VERSION 5.7 ;
  NOWIREEXTENSIONATPIN ON ;
  DIVIDERCHAR "/" ;
  BUSBITCHARS "[]" ;
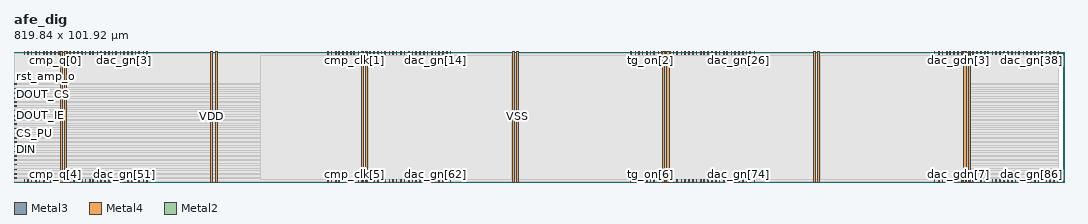
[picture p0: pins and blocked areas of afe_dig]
MACRO afe_dig
  CLASS BLOCK ;
  FOREIGN afe_dig ;
  ORIGIN 0.000 0.000 ;
  SIZE 819.840 BY 101.920 ;
  PIN CS
    DIRECTION INPUT ;
    USE SIGNAL ;
    ANTENNAGATEAREA 25.052999 ;
    PORT
      LAYER Metal3 ;
        RECT 0.000 41.440 2.000 42.000 ;
    END
  END CS
  PIN CS_PD
    DIRECTION OUTPUT ;
    USE SIGNAL ;
    ANTENNADIFFAREA 0.360800 ;
    PORT
      LAYER Metal3 ;
        RECT 0.000 34.160 2.000 34.720 ;
    END
  END CS_PD
  PIN CS_PU
    DIRECTION OUTPUT ;
    USE SIGNAL ;
    ANTENNADIFFAREA 0.360800 ;
    PORT
      LAYER Metal3 ;
        RECT 0.000 37.520 2.000 38.080 ;
    END
  END CS_PU
  PIN DIN
    DIRECTION INPUT ;
    USE SIGNAL ;
    ANTENNAGATEAREA 1.102000 ;
    PORT
      LAYER Metal3 ;
        RECT 0.000 30.800 2.000 31.360 ;
    END
  END DIN
  PIN DIN_PD
    DIRECTION OUTPUT ;
    USE SIGNAL ;
    ANTENNADIFFAREA 0.360800 ;
    PORT
      LAYER Metal3 ;
        RECT 0.000 23.520 2.000 24.080 ;
    END
  END DIN_PD
  PIN DIN_PU
    DIRECTION OUTPUT ;
    USE SIGNAL ;
    ANTENNADIFFAREA 0.360800 ;
    PORT
      LAYER Metal3 ;
        RECT 0.000 27.440 2.000 28.000 ;
    END
  END DIN_PU
  PIN DOUT
    DIRECTION OUTPUT ;
    USE SIGNAL ;
    ANTENNADIFFAREA 2.080000 ;
    PORT
      LAYER Metal3 ;
        RECT 0.000 44.800 2.000 45.360 ;
    END
  END DOUT
  PIN DOUT_CS
    DIRECTION OUTPUT ;
    USE SIGNAL ;
    ANTENNADIFFAREA 0.360800 ;
    PORT
      LAYER Metal3 ;
        RECT 0.000 62.160 2.000 62.720 ;
    END
  END DOUT_CS
  PIN DOUT_IE
    DIRECTION OUTPUT ;
    USE SIGNAL ;
    ANTENNADIFFAREA 0.360800 ;
    PORT
      LAYER Metal3 ;
        RECT 0.000 51.520 2.000 52.080 ;
    END
  END DOUT_IE
  PIN DOUT_OE
    DIRECTION OUTPUT ;
    USE SIGNAL ;
    ANTENNADIFFAREA 10.059999 ;
    PORT
      LAYER Metal3 ;
        RECT 0.000 48.160 2.000 48.720 ;
    END
  END DOUT_OE
  PIN DOUT_PD
    DIRECTION OUTPUT ;
    USE SIGNAL ;
    ANTENNADIFFAREA 0.360800 ;
    PORT
      LAYER Metal3 ;
        RECT 0.000 55.440 2.000 56.000 ;
    END
  END DOUT_PD
  PIN DOUT_PDRV0
    DIRECTION OUTPUT ;
    USE SIGNAL ;
    ANTENNADIFFAREA 0.360800 ;
    PORT
      LAYER Metal3 ;
        RECT 0.000 69.440 2.000 70.000 ;
    END
  END DOUT_PDRV0
  PIN DOUT_PDRV1
    DIRECTION OUTPUT ;
    USE SIGNAL ;
    ANTENNADIFFAREA 0.360800 ;
    PORT
      LAYER Metal3 ;
        RECT 0.000 72.800 2.000 73.360 ;
    END
  END DOUT_PDRV1
  PIN DOUT_PU
    DIRECTION OUTPUT ;
    USE SIGNAL ;
    ANTENNADIFFAREA 0.360800 ;
    PORT
      LAYER Metal3 ;
        RECT 0.000 58.800 2.000 59.360 ;
    END
  END DOUT_PU
  PIN DOUT_SL
    DIRECTION OUTPUT ;
    USE SIGNAL ;
    ANTENNADIFFAREA 0.360800 ;
    PORT
      LAYER Metal3 ;
        RECT 0.000 65.520 2.000 66.080 ;
    END
  END DOUT_SL
  PIN RSTN
    DIRECTION INPUT ;
    USE SIGNAL ;
    ANTENNAGATEAREA 177.865494 ;
    PORT
      LAYER Metal3 ;
        RECT 0.000 9.520 2.000 10.080 ;
    END
  END RSTN
  PIN RSTN_PD
    DIRECTION OUTPUT ;
    USE SIGNAL ;
    ANTENNADIFFAREA 0.536800 ;
    PORT
      LAYER Metal3 ;
        RECT 0.000 2.800 2.000 3.360 ;
    END
  END RSTN_PD
  PIN RSTN_PU
    DIRECTION OUTPUT ;
    USE SIGNAL ;
    ANTENNADIFFAREA 0.360800 ;
    PORT
      LAYER Metal3 ;
        RECT 0.000 6.160 2.000 6.720 ;
    END
  END RSTN_PU
  PIN SCLK
    DIRECTION INPUT ;
    USE SIGNAL ;
    ANTENNAGATEAREA 5.924000 ;
    PORT
      LAYER Metal3 ;
        RECT 0.000 20.160 2.000 20.720 ;
    END
  END SCLK
  PIN SCLK_PD
    DIRECTION OUTPUT ;
    USE SIGNAL ;
    ANTENNADIFFAREA 0.360800 ;
    PORT
      LAYER Metal3 ;
        RECT 0.000 13.440 2.000 14.000 ;
    END
  END SCLK_PD
  PIN SCLK_PU
    DIRECTION OUTPUT ;
    USE SIGNAL ;
    ANTENNADIFFAREA 0.360800 ;
    PORT
      LAYER Metal3 ;
        RECT 0.000 16.800 2.000 17.360 ;
    END
  END SCLK_PU
  PIN VDD
    DIRECTION INOUT ;
    USE POWER ;
    PORT
      LAYER Metal4 ;
        RECT 36.160 0.000 37.760 101.920 ;
    END
    PORT
      LAYER Metal4 ;
        RECT 153.760 0.000 155.360 101.920 ;
    END
    PORT
      LAYER Metal4 ;
        RECT 271.360 0.000 272.960 101.920 ;
    END
    PORT
      LAYER Metal4 ;
        RECT 388.960 0.000 390.560 101.920 ;
    END
    PORT
      LAYER Metal4 ;
        RECT 506.560 0.000 508.160 101.920 ;
    END
    PORT
      LAYER Metal4 ;
        RECT 624.160 0.000 625.760 101.920 ;
    END
    PORT
      LAYER Metal4 ;
        RECT 741.760 0.000 743.360 101.920 ;
    END
  END VDD
  PIN VSS
    DIRECTION INOUT ;
    USE GROUND ;
    PORT
      LAYER Metal4 ;
        RECT 39.460 0.000 41.060 101.920 ;
    END
    PORT
      LAYER Metal4 ;
        RECT 157.060 0.000 158.660 101.920 ;
    END
    PORT
      LAYER Metal4 ;
        RECT 274.660 0.000 276.260 101.920 ;
    END
    PORT
      LAYER Metal4 ;
        RECT 392.260 0.000 393.860 101.920 ;
    END
    PORT
      LAYER Metal4 ;
        RECT 509.860 0.000 511.460 101.920 ;
    END
    PORT
      LAYER Metal4 ;
        RECT 627.460 0.000 629.060 101.920 ;
    END
    PORT
      LAYER Metal4 ;
        RECT 745.060 0.000 746.660 101.920 ;
    END
  END VSS
  PIN cmp_clk[0]
    DIRECTION OUTPUT ;
    USE SIGNAL ;
    ANTENNADIFFAREA 0.875600 ;
    PORT
      LAYER Metal2 ;
        RECT 28.560 99.920 29.120 101.920 ;
    END
  END cmp_clk[0]
  PIN cmp_clk[1]
    DIRECTION OUTPUT ;
    USE SIGNAL ;
    ANTENNADIFFAREA 0.875600 ;
    PORT
      LAYER Metal2 ;
        RECT 265.440 99.920 266.000 101.920 ;
    END
  END cmp_clk[1]
  PIN cmp_clk[2]
    DIRECTION OUTPUT ;
    USE SIGNAL ;
    ANTENNADIFFAREA 0.875600 ;
    PORT
      LAYER Metal2 ;
        RECT 502.880 99.920 503.440 101.920 ;
    END
  END cmp_clk[2]
  PIN cmp_clk[3]
    DIRECTION OUTPUT ;
    USE SIGNAL ;
    ANTENNADIFFAREA 0.875600 ;
    PORT
      LAYER Metal2 ;
        RECT 739.760 99.920 740.320 101.920 ;
    END
  END cmp_clk[3]
  PIN cmp_clk[4]
    DIRECTION OUTPUT ;
    USE SIGNAL ;
    ANTENNADIFFAREA 0.875600 ;
    PORT
      LAYER Metal2 ;
        RECT 28.560 0.000 29.120 2.000 ;
    END
  END cmp_clk[4]
  PIN cmp_clk[5]
    DIRECTION OUTPUT ;
    USE SIGNAL ;
    ANTENNADIFFAREA 0.875600 ;
    PORT
      LAYER Metal2 ;
        RECT 265.440 0.000 266.000 2.000 ;
    END
  END cmp_clk[5]
  PIN cmp_clk[6]
    DIRECTION OUTPUT ;
    USE SIGNAL ;
    ANTENNADIFFAREA 0.875600 ;
    PORT
      LAYER Metal2 ;
        RECT 502.880 0.000 503.440 2.000 ;
    END
  END cmp_clk[6]
  PIN cmp_clk[7]
    DIRECTION OUTPUT ;
    USE SIGNAL ;
    ANTENNADIFFAREA 0.875600 ;
    PORT
      LAYER Metal2 ;
        RECT 739.760 0.000 740.320 2.000 ;
    END
  END cmp_clk[7]
  PIN cmp_q[0]
    DIRECTION INPUT ;
    USE SIGNAL ;
    ANTENNAGATEAREA 0.396000 ;
    PORT
      LAYER Metal2 ;
        RECT 31.920 99.920 32.480 101.920 ;
    END
  END cmp_q[0]
  PIN cmp_q[1]
    DIRECTION INPUT ;
    USE SIGNAL ;
    ANTENNAGATEAREA 0.396000 ;
    PORT
      LAYER Metal2 ;
        RECT 268.800 99.920 269.360 101.920 ;
    END
  END cmp_q[1]
  PIN cmp_q[2]
    DIRECTION INPUT ;
    USE SIGNAL ;
    ANTENNAGATEAREA 0.396000 ;
    PORT
      LAYER Metal2 ;
        RECT 505.680 99.920 506.240 101.920 ;
    END
  END cmp_q[2]
  PIN cmp_q[3]
    DIRECTION INPUT ;
    USE SIGNAL ;
    ANTENNAGATEAREA 0.396000 ;
    PORT
      LAYER Metal2 ;
        RECT 742.560 99.920 743.120 101.920 ;
    END
  END cmp_q[3]
  PIN cmp_q[4]
    DIRECTION INPUT ;
    USE SIGNAL ;
    ANTENNAGATEAREA 0.396000 ;
    PORT
      LAYER Metal2 ;
        RECT 31.920 0.000 32.480 2.000 ;
    END
  END cmp_q[4]
  PIN cmp_q[5]
    DIRECTION INPUT ;
    USE SIGNAL ;
    ANTENNAGATEAREA 0.396000 ;
    PORT
      LAYER Metal2 ;
        RECT 268.800 0.000 269.360 2.000 ;
    END
  END cmp_q[5]
  PIN cmp_q[6]
    DIRECTION INPUT ;
    USE SIGNAL ;
    ANTENNAGATEAREA 0.396000 ;
    PORT
      LAYER Metal2 ;
        RECT 505.680 0.000 506.240 2.000 ;
    END
  END cmp_q[6]
  PIN cmp_q[7]
    DIRECTION INPUT ;
    USE SIGNAL ;
    ANTENNAGATEAREA 0.396000 ;
    PORT
      LAYER Metal2 ;
        RECT 742.560 0.000 743.120 2.000 ;
    END
  END cmp_q[7]
  PIN dac_gdn[0]
    DIRECTION OUTPUT ;
    USE SIGNAL ;
    ANTENNADIFFAREA 0.748000 ;
    PORT
      LAYER Metal2 ;
        RECT 25.760 99.920 26.320 101.920 ;
    END
  END dac_gdn[0]
  PIN dac_gdn[1]
    DIRECTION OUTPUT ;
    USE SIGNAL ;
    ANTENNADIFFAREA 0.748000 ;
    PORT
      LAYER Metal2 ;
        RECT 262.640 99.920 263.200 101.920 ;
    END
  END dac_gdn[1]
  PIN dac_gdn[2]
    DIRECTION OUTPUT ;
    USE SIGNAL ;
    ANTENNADIFFAREA 0.748000 ;
    PORT
      LAYER Metal2 ;
        RECT 499.520 99.920 500.080 101.920 ;
    END
  END dac_gdn[2]
  PIN dac_gdn[3]
    DIRECTION OUTPUT ;
    USE SIGNAL ;
    ANTENNADIFFAREA 0.748000 ;
    PORT
      LAYER Metal2 ;
        RECT 736.960 99.920 737.520 101.920 ;
    END
  END dac_gdn[3]
  PIN dac_gdn[4]
    DIRECTION OUTPUT ;
    USE SIGNAL ;
    ANTENNADIFFAREA 0.748000 ;
    PORT
      LAYER Metal2 ;
        RECT 25.760 0.000 26.320 2.000 ;
    END
  END dac_gdn[4]
  PIN dac_gdn[5]
    DIRECTION OUTPUT ;
    USE SIGNAL ;
    ANTENNADIFFAREA 0.748000 ;
    PORT
      LAYER Metal2 ;
        RECT 262.640 0.000 263.200 2.000 ;
    END
  END dac_gdn[5]
  PIN dac_gdn[6]
    DIRECTION OUTPUT ;
    USE SIGNAL ;
    ANTENNADIFFAREA 0.748000 ;
    PORT
      LAYER Metal2 ;
        RECT 499.520 0.000 500.080 2.000 ;
    END
  END dac_gdn[6]
  PIN dac_gdn[7]
    DIRECTION OUTPUT ;
    USE SIGNAL ;
    ANTENNADIFFAREA 0.748000 ;
    PORT
      LAYER Metal2 ;
        RECT 736.960 0.000 737.520 2.000 ;
    END
  END dac_gdn[7]
  PIN dac_gn[0]
    DIRECTION OUTPUT ;
    USE SIGNAL ;
    ANTENNADIFFAREA 0.830600 ;
    PORT
      LAYER Metal2 ;
        RECT 103.600 99.920 104.160 101.920 ;
    END
  END dac_gn[0]
  PIN dac_gn[10]
    DIRECTION OUTPUT ;
    USE SIGNAL ;
    ANTENNADIFFAREA 0.830600 ;
    PORT
      LAYER Metal2 ;
        RECT 43.680 99.920 44.240 101.920 ;
    END
  END dac_gn[10]
  PIN dac_gn[11]
    DIRECTION OUTPUT ;
    USE SIGNAL ;
    ANTENNADIFFAREA 0.830600 ;
    PORT
      LAYER Metal2 ;
        RECT 37.520 99.920 38.080 101.920 ;
    END
  END dac_gn[11]
  PIN dac_gn[12]
    DIRECTION OUTPUT ;
    USE SIGNAL ;
    ANTENNADIFFAREA 0.830600 ;
    PORT
      LAYER Metal2 ;
        RECT 340.480 99.920 341.040 101.920 ;
    END
  END dac_gn[12]
  PIN dac_gn[13]
    DIRECTION OUTPUT ;
    USE SIGNAL ;
    ANTENNADIFFAREA 0.830600 ;
    PORT
      LAYER Metal2 ;
        RECT 334.880 99.920 335.440 101.920 ;
    END
  END dac_gn[13]
  PIN dac_gn[14]
    DIRECTION OUTPUT ;
    USE SIGNAL ;
    ANTENNADIFFAREA 0.830600 ;
    PORT
      LAYER Metal2 ;
        RECT 328.720 99.920 329.280 101.920 ;
    END
  END dac_gn[14]
  PIN dac_gn[15]
    DIRECTION OUTPUT ;
    USE SIGNAL ;
    ANTENNADIFFAREA 0.830600 ;
    PORT
      LAYER Metal2 ;
        RECT 322.560 99.920 323.120 101.920 ;
    END
  END dac_gn[15]
  PIN dac_gn[16]
    DIRECTION OUTPUT ;
    USE SIGNAL ;
    ANTENNADIFFAREA 0.830600 ;
    PORT
      LAYER Metal2 ;
        RECT 316.960 99.920 317.520 101.920 ;
    END
  END dac_gn[16]
  PIN dac_gn[17]
    DIRECTION OUTPUT ;
    USE SIGNAL ;
    ANTENNADIFFAREA 0.830600 ;
    PORT
      LAYER Metal2 ;
        RECT 310.800 99.920 311.360 101.920 ;
    END
  END dac_gn[17]
  PIN dac_gn[18]
    DIRECTION OUTPUT ;
    USE SIGNAL ;
    ANTENNADIFFAREA 0.830600 ;
    PORT
      LAYER Metal2 ;
        RECT 304.640 99.920 305.200 101.920 ;
    END
  END dac_gn[18]
  PIN dac_gn[19]
    DIRECTION OUTPUT ;
    USE SIGNAL ;
    ANTENNADIFFAREA 0.830600 ;
    PORT
      LAYER Metal2 ;
        RECT 298.480 99.920 299.040 101.920 ;
    END
  END dac_gn[19]
  PIN dac_gn[1]
    DIRECTION OUTPUT ;
    USE SIGNAL ;
    ANTENNADIFFAREA 0.830600 ;
    PORT
      LAYER Metal2 ;
        RECT 97.440 99.920 98.000 101.920 ;
    END
  END dac_gn[1]
  PIN dac_gn[20]
    DIRECTION OUTPUT ;
    USE SIGNAL ;
    ANTENNADIFFAREA 0.830600 ;
    PORT
      LAYER Metal2 ;
        RECT 292.880 99.920 293.440 101.920 ;
    END
  END dac_gn[20]
  PIN dac_gn[21]
    DIRECTION OUTPUT ;
    USE SIGNAL ;
    ANTENNADIFFAREA 0.830600 ;
    PORT
      LAYER Metal2 ;
        RECT 286.720 99.920 287.280 101.920 ;
    END
  END dac_gn[21]
  PIN dac_gn[22]
    DIRECTION OUTPUT ;
    USE SIGNAL ;
    ANTENNADIFFAREA 0.830600 ;
    PORT
      LAYER Metal2 ;
        RECT 280.560 99.920 281.120 101.920 ;
    END
  END dac_gn[22]
  PIN dac_gn[23]
    DIRECTION OUTPUT ;
    USE SIGNAL ;
    ANTENNADIFFAREA 0.830600 ;
    PORT
      LAYER Metal2 ;
        RECT 274.960 99.920 275.520 101.920 ;
    END
  END dac_gn[23]
  PIN dac_gn[24]
    DIRECTION OUTPUT ;
    USE SIGNAL ;
    ANTENNADIFFAREA 0.830600 ;
    PORT
      LAYER Metal2 ;
        RECT 577.920 99.920 578.480 101.920 ;
    END
  END dac_gn[24]
  PIN dac_gn[25]
    DIRECTION OUTPUT ;
    USE SIGNAL ;
    ANTENNADIFFAREA 0.830600 ;
    PORT
      LAYER Metal2 ;
        RECT 571.760 99.920 572.320 101.920 ;
    END
  END dac_gn[25]
  PIN dac_gn[26]
    DIRECTION OUTPUT ;
    USE SIGNAL ;
    ANTENNADIFFAREA 0.830600 ;
    PORT
      LAYER Metal2 ;
        RECT 565.600 99.920 566.160 101.920 ;
    END
  END dac_gn[26]
  PIN dac_gn[27]
    DIRECTION OUTPUT ;
    USE SIGNAL ;
    ANTENNADIFFAREA 0.830600 ;
    PORT
      LAYER Metal2 ;
        RECT 560.000 99.920 560.560 101.920 ;
    END
  END dac_gn[27]
  PIN dac_gn[28]
    DIRECTION OUTPUT ;
    USE SIGNAL ;
    ANTENNADIFFAREA 0.830600 ;
    PORT
      LAYER Metal2 ;
        RECT 553.840 99.920 554.400 101.920 ;
    END
  END dac_gn[28]
  PIN dac_gn[29]
    DIRECTION OUTPUT ;
    USE SIGNAL ;
    ANTENNADIFFAREA 0.830600 ;
    PORT
      LAYER Metal2 ;
        RECT 547.680 99.920 548.240 101.920 ;
    END
  END dac_gn[29]
  PIN dac_gn[2]
    DIRECTION OUTPUT ;
    USE SIGNAL ;
    ANTENNADIFFAREA 0.830600 ;
    PORT
      LAYER Metal2 ;
        RECT 91.840 99.920 92.400 101.920 ;
    END
  END dac_gn[2]
  PIN dac_gn[30]
    DIRECTION OUTPUT ;
    USE SIGNAL ;
    ANTENNADIFFAREA 0.830600 ;
    PORT
      LAYER Metal2 ;
        RECT 541.520 99.920 542.080 101.920 ;
    END
  END dac_gn[30]
  PIN dac_gn[31]
    DIRECTION OUTPUT ;
    USE SIGNAL ;
    ANTENNADIFFAREA 0.830600 ;
    PORT
      LAYER Metal2 ;
        RECT 535.920 99.920 536.480 101.920 ;
    END
  END dac_gn[31]
  PIN dac_gn[32]
    DIRECTION OUTPUT ;
    USE SIGNAL ;
    ANTENNADIFFAREA 0.830600 ;
    PORT
      LAYER Metal2 ;
        RECT 529.760 99.920 530.320 101.920 ;
    END
  END dac_gn[32]
  PIN dac_gn[33]
    DIRECTION OUTPUT ;
    USE SIGNAL ;
    ANTENNADIFFAREA 0.830600 ;
    PORT
      LAYER Metal2 ;
        RECT 523.600 99.920 524.160 101.920 ;
    END
  END dac_gn[33]
  PIN dac_gn[34]
    DIRECTION OUTPUT ;
    USE SIGNAL ;
    ANTENNADIFFAREA 0.830600 ;
    PORT
      LAYER Metal2 ;
        RECT 517.440 99.920 518.000 101.920 ;
    END
  END dac_gn[34]
  PIN dac_gn[35]
    DIRECTION OUTPUT ;
    USE SIGNAL ;
    ANTENNADIFFAREA 0.830600 ;
    PORT
      LAYER Metal2 ;
        RECT 511.840 99.920 512.400 101.920 ;
    END
  END dac_gn[35]
  PIN dac_gn[36]
    DIRECTION OUTPUT ;
    USE SIGNAL ;
    ANTENNADIFFAREA 0.830600 ;
    PORT
      LAYER Metal2 ;
        RECT 814.800 99.920 815.360 101.920 ;
    END
  END dac_gn[36]
  PIN dac_gn[37]
    DIRECTION OUTPUT ;
    USE SIGNAL ;
    ANTENNADIFFAREA 0.830600 ;
    PORT
      LAYER Metal2 ;
        RECT 808.640 99.920 809.200 101.920 ;
    END
  END dac_gn[37]
  PIN dac_gn[38]
    DIRECTION OUTPUT ;
    USE SIGNAL ;
    ANTENNADIFFAREA 0.830600 ;
    PORT
      LAYER Metal2 ;
        RECT 802.480 99.920 803.040 101.920 ;
    END
  END dac_gn[38]
  PIN dac_gn[39]
    DIRECTION OUTPUT ;
    USE SIGNAL ;
    ANTENNADIFFAREA 0.830600 ;
    PORT
      LAYER Metal2 ;
        RECT 796.880 99.920 797.440 101.920 ;
    END
  END dac_gn[39]
  PIN dac_gn[3]
    DIRECTION OUTPUT ;
    USE SIGNAL ;
    ANTENNADIFFAREA 0.830600 ;
    PORT
      LAYER Metal2 ;
        RECT 85.680 99.920 86.240 101.920 ;
    END
  END dac_gn[3]
  PIN dac_gn[40]
    DIRECTION OUTPUT ;
    USE SIGNAL ;
    ANTENNADIFFAREA 0.830600 ;
    PORT
      LAYER Metal2 ;
        RECT 790.720 99.920 791.280 101.920 ;
    END
  END dac_gn[40]
  PIN dac_gn[41]
    DIRECTION OUTPUT ;
    USE SIGNAL ;
    ANTENNADIFFAREA 0.830600 ;
    PORT
      LAYER Metal2 ;
        RECT 784.560 99.920 785.120 101.920 ;
    END
  END dac_gn[41]
  PIN dac_gn[42]
    DIRECTION OUTPUT ;
    USE SIGNAL ;
    ANTENNADIFFAREA 0.830600 ;
    PORT
      LAYER Metal2 ;
        RECT 778.960 99.920 779.520 101.920 ;
    END
  END dac_gn[42]
  PIN dac_gn[43]
    DIRECTION OUTPUT ;
    USE SIGNAL ;
    ANTENNADIFFAREA 0.830600 ;
    PORT
      LAYER Metal2 ;
        RECT 772.800 99.920 773.360 101.920 ;
    END
  END dac_gn[43]
  PIN dac_gn[44]
    DIRECTION OUTPUT ;
    USE SIGNAL ;
    ANTENNADIFFAREA 0.830600 ;
    PORT
      LAYER Metal2 ;
        RECT 766.640 99.920 767.200 101.920 ;
    END
  END dac_gn[44]
  PIN dac_gn[45]
    DIRECTION OUTPUT ;
    USE SIGNAL ;
    ANTENNADIFFAREA 0.830600 ;
    PORT
      LAYER Metal2 ;
        RECT 760.480 99.920 761.040 101.920 ;
    END
  END dac_gn[45]
  PIN dac_gn[46]
    DIRECTION OUTPUT ;
    USE SIGNAL ;
    ANTENNADIFFAREA 0.830600 ;
    PORT
      LAYER Metal2 ;
        RECT 754.880 99.920 755.440 101.920 ;
    END
  END dac_gn[46]
  PIN dac_gn[47]
    DIRECTION OUTPUT ;
    USE SIGNAL ;
    ANTENNADIFFAREA 0.830600 ;
    PORT
      LAYER Metal2 ;
        RECT 748.720 99.920 749.280 101.920 ;
    END
  END dac_gn[47]
  PIN dac_gn[48]
    DIRECTION OUTPUT ;
    USE SIGNAL ;
    ANTENNADIFFAREA 0.830600 ;
    PORT
      LAYER Metal2 ;
        RECT 103.600 0.000 104.160 2.000 ;
    END
  END dac_gn[48]
  PIN dac_gn[49]
    DIRECTION OUTPUT ;
    USE SIGNAL ;
    ANTENNADIFFAREA 0.830600 ;
    PORT
      LAYER Metal2 ;
        RECT 97.440 0.000 98.000 2.000 ;
    END
  END dac_gn[49]
  PIN dac_gn[4]
    DIRECTION OUTPUT ;
    USE SIGNAL ;
    ANTENNADIFFAREA 0.830600 ;
    PORT
      LAYER Metal2 ;
        RECT 79.520 99.920 80.080 101.920 ;
    END
  END dac_gn[4]
  PIN dac_gn[50]
    DIRECTION OUTPUT ;
    USE SIGNAL ;
    ANTENNADIFFAREA 0.830600 ;
    PORT
      LAYER Metal2 ;
        RECT 91.840 0.000 92.400 2.000 ;
    END
  END dac_gn[50]
  PIN dac_gn[51]
    DIRECTION OUTPUT ;
    USE SIGNAL ;
    ANTENNADIFFAREA 0.830600 ;
    PORT
      LAYER Metal2 ;
        RECT 85.680 0.000 86.240 2.000 ;
    END
  END dac_gn[51]
  PIN dac_gn[52]
    DIRECTION OUTPUT ;
    USE SIGNAL ;
    ANTENNADIFFAREA 0.830600 ;
    PORT
      LAYER Metal2 ;
        RECT 79.520 0.000 80.080 2.000 ;
    END
  END dac_gn[52]
  PIN dac_gn[53]
    DIRECTION OUTPUT ;
    USE SIGNAL ;
    ANTENNADIFFAREA 0.830600 ;
    PORT
      LAYER Metal2 ;
        RECT 73.920 0.000 74.480 2.000 ;
    END
  END dac_gn[53]
  PIN dac_gn[54]
    DIRECTION OUTPUT ;
    USE SIGNAL ;
    ANTENNADIFFAREA 0.830600 ;
    PORT
      LAYER Metal2 ;
        RECT 67.760 0.000 68.320 2.000 ;
    END
  END dac_gn[54]
  PIN dac_gn[55]
    DIRECTION OUTPUT ;
    USE SIGNAL ;
    ANTENNADIFFAREA 0.830600 ;
    PORT
      LAYER Metal2 ;
        RECT 61.600 0.000 62.160 2.000 ;
    END
  END dac_gn[55]
  PIN dac_gn[56]
    DIRECTION OUTPUT ;
    USE SIGNAL ;
    ANTENNADIFFAREA 0.830600 ;
    PORT
      LAYER Metal2 ;
        RECT 55.440 0.000 56.000 2.000 ;
    END
  END dac_gn[56]
  PIN dac_gn[57]
    DIRECTION OUTPUT ;
    USE SIGNAL ;
    ANTENNADIFFAREA 0.830600 ;
    PORT
      LAYER Metal2 ;
        RECT 49.840 0.000 50.400 2.000 ;
    END
  END dac_gn[57]
  PIN dac_gn[58]
    DIRECTION OUTPUT ;
    USE SIGNAL ;
    ANTENNADIFFAREA 0.830600 ;
    PORT
      LAYER Metal2 ;
        RECT 43.680 0.000 44.240 2.000 ;
    END
  END dac_gn[58]
  PIN dac_gn[59]
    DIRECTION OUTPUT ;
    USE SIGNAL ;
    ANTENNADIFFAREA 0.830600 ;
    PORT
      LAYER Metal2 ;
        RECT 37.520 0.000 38.080 2.000 ;
    END
  END dac_gn[59]
  PIN dac_gn[5]
    DIRECTION OUTPUT ;
    USE SIGNAL ;
    ANTENNADIFFAREA 0.830600 ;
    PORT
      LAYER Metal2 ;
        RECT 73.920 99.920 74.480 101.920 ;
    END
  END dac_gn[5]
  PIN dac_gn[60]
    DIRECTION OUTPUT ;
    USE SIGNAL ;
    ANTENNADIFFAREA 0.830600 ;
    PORT
      LAYER Metal2 ;
        RECT 340.480 0.000 341.040 2.000 ;
    END
  END dac_gn[60]
  PIN dac_gn[61]
    DIRECTION OUTPUT ;
    USE SIGNAL ;
    ANTENNADIFFAREA 0.830600 ;
    PORT
      LAYER Metal2 ;
        RECT 334.880 0.000 335.440 2.000 ;
    END
  END dac_gn[61]
  PIN dac_gn[62]
    DIRECTION OUTPUT ;
    USE SIGNAL ;
    ANTENNADIFFAREA 0.830600 ;
    PORT
      LAYER Metal2 ;
        RECT 328.720 0.000 329.280 2.000 ;
    END
  END dac_gn[62]
  PIN dac_gn[63]
    DIRECTION OUTPUT ;
    USE SIGNAL ;
    ANTENNADIFFAREA 0.830600 ;
    PORT
      LAYER Metal2 ;
        RECT 322.560 0.000 323.120 2.000 ;
    END
  END dac_gn[63]
  PIN dac_gn[64]
    DIRECTION OUTPUT ;
    USE SIGNAL ;
    ANTENNADIFFAREA 0.830600 ;
    PORT
      LAYER Metal2 ;
        RECT 316.960 0.000 317.520 2.000 ;
    END
  END dac_gn[64]
  PIN dac_gn[65]
    DIRECTION OUTPUT ;
    USE SIGNAL ;
    ANTENNADIFFAREA 0.830600 ;
    PORT
      LAYER Metal2 ;
        RECT 310.800 0.000 311.360 2.000 ;
    END
  END dac_gn[65]
  PIN dac_gn[66]
    DIRECTION OUTPUT ;
    USE SIGNAL ;
    ANTENNADIFFAREA 0.830600 ;
    PORT
      LAYER Metal2 ;
        RECT 304.640 0.000 305.200 2.000 ;
    END
  END dac_gn[66]
  PIN dac_gn[67]
    DIRECTION OUTPUT ;
    USE SIGNAL ;
    ANTENNADIFFAREA 0.830600 ;
    PORT
      LAYER Metal2 ;
        RECT 298.480 0.000 299.040 2.000 ;
    END
  END dac_gn[67]
  PIN dac_gn[68]
    DIRECTION OUTPUT ;
    USE SIGNAL ;
    ANTENNADIFFAREA 0.830600 ;
    PORT
      LAYER Metal2 ;
        RECT 292.880 0.000 293.440 2.000 ;
    END
  END dac_gn[68]
  PIN dac_gn[69]
    DIRECTION OUTPUT ;
    USE SIGNAL ;
    ANTENNADIFFAREA 0.830600 ;
    PORT
      LAYER Metal2 ;
        RECT 286.720 0.000 287.280 2.000 ;
    END
  END dac_gn[69]
  PIN dac_gn[6]
    DIRECTION OUTPUT ;
    USE SIGNAL ;
    ANTENNADIFFAREA 0.830600 ;
    PORT
      LAYER Metal2 ;
        RECT 67.760 99.920 68.320 101.920 ;
    END
  END dac_gn[6]
  PIN dac_gn[70]
    DIRECTION OUTPUT ;
    USE SIGNAL ;
    ANTENNADIFFAREA 0.830600 ;
    PORT
      LAYER Metal2 ;
        RECT 280.560 0.000 281.120 2.000 ;
    END
  END dac_gn[70]
  PIN dac_gn[71]
    DIRECTION OUTPUT ;
    USE SIGNAL ;
    ANTENNADIFFAREA 0.830600 ;
    PORT
      LAYER Metal2 ;
        RECT 274.960 0.000 275.520 2.000 ;
    END
  END dac_gn[71]
  PIN dac_gn[72]
    DIRECTION OUTPUT ;
    USE SIGNAL ;
    ANTENNADIFFAREA 0.830600 ;
    PORT
      LAYER Metal2 ;
        RECT 577.920 0.000 578.480 2.000 ;
    END
  END dac_gn[72]
  PIN dac_gn[73]
    DIRECTION OUTPUT ;
    USE SIGNAL ;
    ANTENNADIFFAREA 0.830600 ;
    PORT
      LAYER Metal2 ;
        RECT 571.760 0.000 572.320 2.000 ;
    END
  END dac_gn[73]
  PIN dac_gn[74]
    DIRECTION OUTPUT ;
    USE SIGNAL ;
    ANTENNADIFFAREA 0.830600 ;
    PORT
      LAYER Metal2 ;
        RECT 565.600 0.000 566.160 2.000 ;
    END
  END dac_gn[74]
  PIN dac_gn[75]
    DIRECTION OUTPUT ;
    USE SIGNAL ;
    ANTENNADIFFAREA 0.830600 ;
    PORT
      LAYER Metal2 ;
        RECT 560.000 0.000 560.560 2.000 ;
    END
  END dac_gn[75]
  PIN dac_gn[76]
    DIRECTION OUTPUT ;
    USE SIGNAL ;
    ANTENNADIFFAREA 0.830600 ;
    PORT
      LAYER Metal2 ;
        RECT 553.840 0.000 554.400 2.000 ;
    END
  END dac_gn[76]
  PIN dac_gn[77]
    DIRECTION OUTPUT ;
    USE SIGNAL ;
    ANTENNADIFFAREA 0.830600 ;
    PORT
      LAYER Metal2 ;
        RECT 547.680 0.000 548.240 2.000 ;
    END
  END dac_gn[77]
  PIN dac_gn[78]
    DIRECTION OUTPUT ;
    USE SIGNAL ;
    ANTENNADIFFAREA 0.830600 ;
    PORT
      LAYER Metal2 ;
        RECT 541.520 0.000 542.080 2.000 ;
    END
  END dac_gn[78]
  PIN dac_gn[79]
    DIRECTION OUTPUT ;
    USE SIGNAL ;
    ANTENNADIFFAREA 0.830600 ;
    PORT
      LAYER Metal2 ;
        RECT 535.920 0.000 536.480 2.000 ;
    END
  END dac_gn[79]
  PIN dac_gn[7]
    DIRECTION OUTPUT ;
    USE SIGNAL ;
    ANTENNADIFFAREA 0.830600 ;
    PORT
      LAYER Metal2 ;
        RECT 61.600 99.920 62.160 101.920 ;
    END
  END dac_gn[7]
  PIN dac_gn[80]
    DIRECTION OUTPUT ;
    USE SIGNAL ;
    ANTENNADIFFAREA 0.830600 ;
    PORT
      LAYER Metal2 ;
        RECT 529.760 0.000 530.320 2.000 ;
    END
  END dac_gn[80]
  PIN dac_gn[81]
    DIRECTION OUTPUT ;
    USE SIGNAL ;
    ANTENNADIFFAREA 0.830600 ;
    PORT
      LAYER Metal2 ;
        RECT 523.600 0.000 524.160 2.000 ;
    END
  END dac_gn[81]
  PIN dac_gn[82]
    DIRECTION OUTPUT ;
    USE SIGNAL ;
    ANTENNADIFFAREA 0.830600 ;
    PORT
      LAYER Metal2 ;
        RECT 517.440 0.000 518.000 2.000 ;
    END
  END dac_gn[82]
  PIN dac_gn[83]
    DIRECTION OUTPUT ;
    USE SIGNAL ;
    ANTENNADIFFAREA 0.830600 ;
    PORT
      LAYER Metal2 ;
        RECT 511.840 0.000 512.400 2.000 ;
    END
  END dac_gn[83]
  PIN dac_gn[84]
    DIRECTION OUTPUT ;
    USE SIGNAL ;
    ANTENNADIFFAREA 0.830600 ;
    PORT
      LAYER Metal2 ;
        RECT 814.800 0.000 815.360 2.000 ;
    END
  END dac_gn[84]
  PIN dac_gn[85]
    DIRECTION OUTPUT ;
    USE SIGNAL ;
    ANTENNADIFFAREA 0.830600 ;
    PORT
      LAYER Metal2 ;
        RECT 808.640 0.000 809.200 2.000 ;
    END
  END dac_gn[85]
  PIN dac_gn[86]
    DIRECTION OUTPUT ;
    USE SIGNAL ;
    ANTENNADIFFAREA 0.830600 ;
    PORT
      LAYER Metal2 ;
        RECT 802.480 0.000 803.040 2.000 ;
    END
  END dac_gn[86]
  PIN dac_gn[87]
    DIRECTION OUTPUT ;
    USE SIGNAL ;
    ANTENNADIFFAREA 0.830600 ;
    PORT
      LAYER Metal2 ;
        RECT 796.880 0.000 797.440 2.000 ;
    END
  END dac_gn[87]
  PIN dac_gn[88]
    DIRECTION OUTPUT ;
    USE SIGNAL ;
    ANTENNADIFFAREA 0.830600 ;
    PORT
      LAYER Metal2 ;
        RECT 790.720 0.000 791.280 2.000 ;
    END
  END dac_gn[88]
  PIN dac_gn[89]
    DIRECTION OUTPUT ;
    USE SIGNAL ;
    ANTENNADIFFAREA 0.830600 ;
    PORT
      LAYER Metal2 ;
        RECT 784.560 0.000 785.120 2.000 ;
    END
  END dac_gn[89]
  PIN dac_gn[8]
    DIRECTION OUTPUT ;
    USE SIGNAL ;
    ANTENNADIFFAREA 0.830600 ;
    PORT
      LAYER Metal2 ;
        RECT 55.440 99.920 56.000 101.920 ;
    END
  END dac_gn[8]
  PIN dac_gn[90]
    DIRECTION OUTPUT ;
    USE SIGNAL ;
    ANTENNADIFFAREA 0.830600 ;
    PORT
      LAYER Metal2 ;
        RECT 778.960 0.000 779.520 2.000 ;
    END
  END dac_gn[90]
  PIN dac_gn[91]
    DIRECTION OUTPUT ;
    USE SIGNAL ;
    ANTENNADIFFAREA 0.830600 ;
    PORT
      LAYER Metal2 ;
        RECT 772.800 0.000 773.360 2.000 ;
    END
  END dac_gn[91]
  PIN dac_gn[92]
    DIRECTION OUTPUT ;
    USE SIGNAL ;
    ANTENNADIFFAREA 0.830600 ;
    PORT
      LAYER Metal2 ;
        RECT 766.640 0.000 767.200 2.000 ;
    END
  END dac_gn[92]
  PIN dac_gn[93]
    DIRECTION OUTPUT ;
    USE SIGNAL ;
    ANTENNADIFFAREA 0.830600 ;
    PORT
      LAYER Metal2 ;
        RECT 760.480 0.000 761.040 2.000 ;
    END
  END dac_gn[93]
  PIN dac_gn[94]
    DIRECTION OUTPUT ;
    USE SIGNAL ;
    ANTENNADIFFAREA 0.830600 ;
    PORT
      LAYER Metal2 ;
        RECT 754.880 0.000 755.440 2.000 ;
    END
  END dac_gn[94]
  PIN dac_gn[95]
    DIRECTION OUTPUT ;
    USE SIGNAL ;
    ANTENNADIFFAREA 0.830600 ;
    PORT
      LAYER Metal2 ;
        RECT 748.720 0.000 749.280 2.000 ;
    END
  END dac_gn[95]
  PIN dac_gn[9]
    DIRECTION OUTPUT ;
    USE SIGNAL ;
    ANTENNADIFFAREA 0.830600 ;
    PORT
      LAYER Metal2 ;
        RECT 49.840 99.920 50.400 101.920 ;
    END
  END dac_gn[9]
  PIN dac_gp[0]
    DIRECTION OUTPUT ;
    USE SIGNAL ;
    ANTENNADIFFAREA 0.948400 ;
    PORT
      LAYER Metal2 ;
        RECT 100.800 99.920 101.360 101.920 ;
    END
  END dac_gp[0]
  PIN dac_gp[10]
    DIRECTION OUTPUT ;
    USE SIGNAL ;
    ANTENNADIFFAREA 0.948400 ;
    PORT
      LAYER Metal2 ;
        RECT 40.880 99.920 41.440 101.920 ;
    END
  END dac_gp[10]
  PIN dac_gp[11]
    DIRECTION OUTPUT ;
    USE SIGNAL ;
    ANTENNADIFFAREA 0.948400 ;
    PORT
      LAYER Metal2 ;
        RECT 34.720 99.920 35.280 101.920 ;
    END
  END dac_gp[11]
  PIN dac_gp[12]
    DIRECTION OUTPUT ;
    USE SIGNAL ;
    ANTENNADIFFAREA 0.948400 ;
    PORT
      LAYER Metal2 ;
        RECT 337.680 99.920 338.240 101.920 ;
    END
  END dac_gp[12]
  PIN dac_gp[13]
    DIRECTION OUTPUT ;
    USE SIGNAL ;
    ANTENNADIFFAREA 0.948400 ;
    PORT
      LAYER Metal2 ;
        RECT 331.520 99.920 332.080 101.920 ;
    END
  END dac_gp[13]
  PIN dac_gp[14]
    DIRECTION OUTPUT ;
    USE SIGNAL ;
    ANTENNADIFFAREA 0.948400 ;
    PORT
      LAYER Metal2 ;
        RECT 325.920 99.920 326.480 101.920 ;
    END
  END dac_gp[14]
  PIN dac_gp[15]
    DIRECTION OUTPUT ;
    USE SIGNAL ;
    ANTENNADIFFAREA 0.948400 ;
    PORT
      LAYER Metal2 ;
        RECT 319.760 99.920 320.320 101.920 ;
    END
  END dac_gp[15]
  PIN dac_gp[16]
    DIRECTION OUTPUT ;
    USE SIGNAL ;
    ANTENNADIFFAREA 0.948400 ;
    PORT
      LAYER Metal2 ;
        RECT 313.600 99.920 314.160 101.920 ;
    END
  END dac_gp[16]
  PIN dac_gp[17]
    DIRECTION OUTPUT ;
    USE SIGNAL ;
    ANTENNADIFFAREA 0.948400 ;
    PORT
      LAYER Metal2 ;
        RECT 308.000 99.920 308.560 101.920 ;
    END
  END dac_gp[17]
  PIN dac_gp[18]
    DIRECTION OUTPUT ;
    USE SIGNAL ;
    ANTENNADIFFAREA 0.948400 ;
    PORT
      LAYER Metal2 ;
        RECT 301.840 99.920 302.400 101.920 ;
    END
  END dac_gp[18]
  PIN dac_gp[19]
    DIRECTION OUTPUT ;
    USE SIGNAL ;
    ANTENNADIFFAREA 0.948400 ;
    PORT
      LAYER Metal2 ;
        RECT 295.680 99.920 296.240 101.920 ;
    END
  END dac_gp[19]
  PIN dac_gp[1]
    DIRECTION OUTPUT ;
    USE SIGNAL ;
    ANTENNADIFFAREA 0.948400 ;
    PORT
      LAYER Metal2 ;
        RECT 94.640 99.920 95.200 101.920 ;
    END
  END dac_gp[1]
  PIN dac_gp[20]
    DIRECTION OUTPUT ;
    USE SIGNAL ;
    ANTENNADIFFAREA 0.948400 ;
    PORT
      LAYER Metal2 ;
        RECT 289.520 99.920 290.080 101.920 ;
    END
  END dac_gp[20]
  PIN dac_gp[21]
    DIRECTION OUTPUT ;
    USE SIGNAL ;
    ANTENNADIFFAREA 0.948400 ;
    PORT
      LAYER Metal2 ;
        RECT 283.920 99.920 284.480 101.920 ;
    END
  END dac_gp[21]
  PIN dac_gp[22]
    DIRECTION OUTPUT ;
    USE SIGNAL ;
    ANTENNADIFFAREA 0.948400 ;
    PORT
      LAYER Metal2 ;
        RECT 277.760 99.920 278.320 101.920 ;
    END
  END dac_gp[22]
  PIN dac_gp[23]
    DIRECTION OUTPUT ;
    USE SIGNAL ;
    ANTENNADIFFAREA 0.948400 ;
    PORT
      LAYER Metal2 ;
        RECT 271.600 99.920 272.160 101.920 ;
    END
  END dac_gp[23]
  PIN dac_gp[24]
    DIRECTION OUTPUT ;
    USE SIGNAL ;
    ANTENNADIFFAREA 0.948400 ;
    PORT
      LAYER Metal2 ;
        RECT 574.560 99.920 575.120 101.920 ;
    END
  END dac_gp[24]
  PIN dac_gp[25]
    DIRECTION OUTPUT ;
    USE SIGNAL ;
    ANTENNADIFFAREA 0.948400 ;
    PORT
      LAYER Metal2 ;
        RECT 568.960 99.920 569.520 101.920 ;
    END
  END dac_gp[25]
  PIN dac_gp[26]
    DIRECTION OUTPUT ;
    USE SIGNAL ;
    ANTENNADIFFAREA 0.948400 ;
    PORT
      LAYER Metal2 ;
        RECT 562.800 99.920 563.360 101.920 ;
    END
  END dac_gp[26]
  PIN dac_gp[27]
    DIRECTION OUTPUT ;
    USE SIGNAL ;
    ANTENNADIFFAREA 0.948400 ;
    PORT
      LAYER Metal2 ;
        RECT 556.640 99.920 557.200 101.920 ;
    END
  END dac_gp[27]
  PIN dac_gp[28]
    DIRECTION OUTPUT ;
    USE SIGNAL ;
    ANTENNADIFFAREA 0.948400 ;
    PORT
      LAYER Metal2 ;
        RECT 550.480 99.920 551.040 101.920 ;
    END
  END dac_gp[28]
  PIN dac_gp[29]
    DIRECTION OUTPUT ;
    USE SIGNAL ;
    ANTENNADIFFAREA 0.948400 ;
    PORT
      LAYER Metal2 ;
        RECT 544.880 99.920 545.440 101.920 ;
    END
  END dac_gp[29]
  PIN dac_gp[2]
    DIRECTION OUTPUT ;
    USE SIGNAL ;
    ANTENNADIFFAREA 0.948400 ;
    PORT
      LAYER Metal2 ;
        RECT 88.480 99.920 89.040 101.920 ;
    END
  END dac_gp[2]
  PIN dac_gp[30]
    DIRECTION OUTPUT ;
    USE SIGNAL ;
    ANTENNADIFFAREA 0.948400 ;
    PORT
      LAYER Metal2 ;
        RECT 538.720 99.920 539.280 101.920 ;
    END
  END dac_gp[30]
  PIN dac_gp[31]
    DIRECTION OUTPUT ;
    USE SIGNAL ;
    ANTENNADIFFAREA 0.948400 ;
    PORT
      LAYER Metal2 ;
        RECT 532.560 99.920 533.120 101.920 ;
    END
  END dac_gp[31]
  PIN dac_gp[32]
    DIRECTION OUTPUT ;
    USE SIGNAL ;
    ANTENNADIFFAREA 0.948400 ;
    PORT
      LAYER Metal2 ;
        RECT 526.960 99.920 527.520 101.920 ;
    END
  END dac_gp[32]
  PIN dac_gp[33]
    DIRECTION OUTPUT ;
    USE SIGNAL ;
    ANTENNADIFFAREA 0.948400 ;
    PORT
      LAYER Metal2 ;
        RECT 520.800 99.920 521.360 101.920 ;
    END
  END dac_gp[33]
  PIN dac_gp[34]
    DIRECTION OUTPUT ;
    USE SIGNAL ;
    ANTENNADIFFAREA 0.948400 ;
    PORT
      LAYER Metal2 ;
        RECT 514.640 99.920 515.200 101.920 ;
    END
  END dac_gp[34]
  PIN dac_gp[35]
    DIRECTION OUTPUT ;
    USE SIGNAL ;
    ANTENNADIFFAREA 0.948400 ;
    PORT
      LAYER Metal2 ;
        RECT 508.480 99.920 509.040 101.920 ;
    END
  END dac_gp[35]
  PIN dac_gp[36]
    DIRECTION OUTPUT ;
    USE SIGNAL ;
    ANTENNADIFFAREA 0.948400 ;
    PORT
      LAYER Metal2 ;
        RECT 812.000 99.920 812.560 101.920 ;
    END
  END dac_gp[36]
  PIN dac_gp[37]
    DIRECTION OUTPUT ;
    USE SIGNAL ;
    ANTENNADIFFAREA 0.948400 ;
    PORT
      LAYER Metal2 ;
        RECT 805.840 99.920 806.400 101.920 ;
    END
  END dac_gp[37]
  PIN dac_gp[38]
    DIRECTION OUTPUT ;
    USE SIGNAL ;
    ANTENNADIFFAREA 0.948400 ;
    PORT
      LAYER Metal2 ;
        RECT 799.680 99.920 800.240 101.920 ;
    END
  END dac_gp[38]
  PIN dac_gp[39]
    DIRECTION OUTPUT ;
    USE SIGNAL ;
    ANTENNADIFFAREA 0.948400 ;
    PORT
      LAYER Metal2 ;
        RECT 793.520 99.920 794.080 101.920 ;
    END
  END dac_gp[39]
  PIN dac_gp[3]
    DIRECTION OUTPUT ;
    USE SIGNAL ;
    ANTENNADIFFAREA 0.948400 ;
    PORT
      LAYER Metal2 ;
        RECT 82.880 99.920 83.440 101.920 ;
    END
  END dac_gp[3]
  PIN dac_gp[40]
    DIRECTION OUTPUT ;
    USE SIGNAL ;
    ANTENNADIFFAREA 0.948400 ;
    PORT
      LAYER Metal2 ;
        RECT 787.920 99.920 788.480 101.920 ;
    END
  END dac_gp[40]
  PIN dac_gp[41]
    DIRECTION OUTPUT ;
    USE SIGNAL ;
    ANTENNADIFFAREA 0.948400 ;
    PORT
      LAYER Metal2 ;
        RECT 781.760 99.920 782.320 101.920 ;
    END
  END dac_gp[41]
  PIN dac_gp[42]
    DIRECTION OUTPUT ;
    USE SIGNAL ;
    ANTENNADIFFAREA 0.948400 ;
    PORT
      LAYER Metal2 ;
        RECT 775.600 99.920 776.160 101.920 ;
    END
  END dac_gp[42]
  PIN dac_gp[43]
    DIRECTION OUTPUT ;
    USE SIGNAL ;
    ANTENNADIFFAREA 0.948400 ;
    PORT
      LAYER Metal2 ;
        RECT 769.440 99.920 770.000 101.920 ;
    END
  END dac_gp[43]
  PIN dac_gp[44]
    DIRECTION OUTPUT ;
    USE SIGNAL ;
    ANTENNADIFFAREA 0.948400 ;
    PORT
      LAYER Metal2 ;
        RECT 763.840 99.920 764.400 101.920 ;
    END
  END dac_gp[44]
  PIN dac_gp[45]
    DIRECTION OUTPUT ;
    USE SIGNAL ;
    ANTENNADIFFAREA 0.948400 ;
    PORT
      LAYER Metal2 ;
        RECT 757.680 99.920 758.240 101.920 ;
    END
  END dac_gp[45]
  PIN dac_gp[46]
    DIRECTION OUTPUT ;
    USE SIGNAL ;
    ANTENNADIFFAREA 0.948400 ;
    PORT
      LAYER Metal2 ;
        RECT 751.520 99.920 752.080 101.920 ;
    END
  END dac_gp[46]
  PIN dac_gp[47]
    DIRECTION OUTPUT ;
    USE SIGNAL ;
    ANTENNADIFFAREA 0.948400 ;
    PORT
      LAYER Metal2 ;
        RECT 745.920 99.920 746.480 101.920 ;
    END
  END dac_gp[47]
  PIN dac_gp[48]
    DIRECTION OUTPUT ;
    USE SIGNAL ;
    ANTENNADIFFAREA 0.948400 ;
    PORT
      LAYER Metal2 ;
        RECT 100.800 0.000 101.360 2.000 ;
    END
  END dac_gp[48]
  PIN dac_gp[49]
    DIRECTION OUTPUT ;
    USE SIGNAL ;
    ANTENNADIFFAREA 0.948400 ;
    PORT
      LAYER Metal2 ;
        RECT 94.640 0.000 95.200 2.000 ;
    END
  END dac_gp[49]
  PIN dac_gp[4]
    DIRECTION OUTPUT ;
    USE SIGNAL ;
    ANTENNADIFFAREA 0.948400 ;
    PORT
      LAYER Metal2 ;
        RECT 76.720 99.920 77.280 101.920 ;
    END
  END dac_gp[4]
  PIN dac_gp[50]
    DIRECTION OUTPUT ;
    USE SIGNAL ;
    ANTENNADIFFAREA 0.948400 ;
    PORT
      LAYER Metal2 ;
        RECT 88.480 0.000 89.040 2.000 ;
    END
  END dac_gp[50]
  PIN dac_gp[51]
    DIRECTION OUTPUT ;
    USE SIGNAL ;
    ANTENNADIFFAREA 0.948400 ;
    PORT
      LAYER Metal2 ;
        RECT 82.880 0.000 83.440 2.000 ;
    END
  END dac_gp[51]
  PIN dac_gp[52]
    DIRECTION OUTPUT ;
    USE SIGNAL ;
    ANTENNADIFFAREA 0.948400 ;
    PORT
      LAYER Metal2 ;
        RECT 76.720 0.000 77.280 2.000 ;
    END
  END dac_gp[52]
  PIN dac_gp[53]
    DIRECTION OUTPUT ;
    USE SIGNAL ;
    ANTENNADIFFAREA 0.948400 ;
    PORT
      LAYER Metal2 ;
        RECT 70.560 0.000 71.120 2.000 ;
    END
  END dac_gp[53]
  PIN dac_gp[54]
    DIRECTION OUTPUT ;
    USE SIGNAL ;
    ANTENNADIFFAREA 0.948400 ;
    PORT
      LAYER Metal2 ;
        RECT 64.960 0.000 65.520 2.000 ;
    END
  END dac_gp[54]
  PIN dac_gp[55]
    DIRECTION OUTPUT ;
    USE SIGNAL ;
    ANTENNADIFFAREA 0.948400 ;
    PORT
      LAYER Metal2 ;
        RECT 58.800 0.000 59.360 2.000 ;
    END
  END dac_gp[55]
  PIN dac_gp[56]
    DIRECTION OUTPUT ;
    USE SIGNAL ;
    ANTENNADIFFAREA 0.948400 ;
    PORT
      LAYER Metal2 ;
        RECT 52.640 0.000 53.200 2.000 ;
    END
  END dac_gp[56]
  PIN dac_gp[57]
    DIRECTION OUTPUT ;
    USE SIGNAL ;
    ANTENNADIFFAREA 0.948400 ;
    PORT
      LAYER Metal2 ;
        RECT 46.480 0.000 47.040 2.000 ;
    END
  END dac_gp[57]
  PIN dac_gp[58]
    DIRECTION OUTPUT ;
    USE SIGNAL ;
    ANTENNADIFFAREA 0.948400 ;
    PORT
      LAYER Metal2 ;
        RECT 40.880 0.000 41.440 2.000 ;
    END
  END dac_gp[58]
  PIN dac_gp[59]
    DIRECTION OUTPUT ;
    USE SIGNAL ;
    ANTENNADIFFAREA 0.948400 ;
    PORT
      LAYER Metal2 ;
        RECT 34.720 0.000 35.280 2.000 ;
    END
  END dac_gp[59]
  PIN dac_gp[5]
    DIRECTION OUTPUT ;
    USE SIGNAL ;
    ANTENNADIFFAREA 0.948400 ;
    PORT
      LAYER Metal2 ;
        RECT 70.560 99.920 71.120 101.920 ;
    END
  END dac_gp[5]
  PIN dac_gp[60]
    DIRECTION OUTPUT ;
    USE SIGNAL ;
    ANTENNADIFFAREA 0.948400 ;
    PORT
      LAYER Metal2 ;
        RECT 337.680 0.000 338.240 2.000 ;
    END
  END dac_gp[60]
  PIN dac_gp[61]
    DIRECTION OUTPUT ;
    USE SIGNAL ;
    ANTENNADIFFAREA 0.948400 ;
    PORT
      LAYER Metal2 ;
        RECT 331.520 0.000 332.080 2.000 ;
    END
  END dac_gp[61]
  PIN dac_gp[62]
    DIRECTION OUTPUT ;
    USE SIGNAL ;
    ANTENNADIFFAREA 0.948400 ;
    PORT
      LAYER Metal2 ;
        RECT 325.920 0.000 326.480 2.000 ;
    END
  END dac_gp[62]
  PIN dac_gp[63]
    DIRECTION OUTPUT ;
    USE SIGNAL ;
    ANTENNADIFFAREA 0.948400 ;
    PORT
      LAYER Metal2 ;
        RECT 319.760 0.000 320.320 2.000 ;
    END
  END dac_gp[63]
  PIN dac_gp[64]
    DIRECTION OUTPUT ;
    USE SIGNAL ;
    ANTENNADIFFAREA 0.948400 ;
    PORT
      LAYER Metal2 ;
        RECT 313.600 0.000 314.160 2.000 ;
    END
  END dac_gp[64]
  PIN dac_gp[65]
    DIRECTION OUTPUT ;
    USE SIGNAL ;
    ANTENNADIFFAREA 0.948400 ;
    PORT
      LAYER Metal2 ;
        RECT 308.000 0.000 308.560 2.000 ;
    END
  END dac_gp[65]
  PIN dac_gp[66]
    DIRECTION OUTPUT ;
    USE SIGNAL ;
    ANTENNADIFFAREA 0.948400 ;
    PORT
      LAYER Metal2 ;
        RECT 301.840 0.000 302.400 2.000 ;
    END
  END dac_gp[66]
  PIN dac_gp[67]
    DIRECTION OUTPUT ;
    USE SIGNAL ;
    ANTENNADIFFAREA 0.948400 ;
    PORT
      LAYER Metal2 ;
        RECT 295.680 0.000 296.240 2.000 ;
    END
  END dac_gp[67]
  PIN dac_gp[68]
    DIRECTION OUTPUT ;
    USE SIGNAL ;
    ANTENNADIFFAREA 0.948400 ;
    PORT
      LAYER Metal2 ;
        RECT 289.520 0.000 290.080 2.000 ;
    END
  END dac_gp[68]
  PIN dac_gp[69]
    DIRECTION OUTPUT ;
    USE SIGNAL ;
    ANTENNADIFFAREA 0.948400 ;
    PORT
      LAYER Metal2 ;
        RECT 283.920 0.000 284.480 2.000 ;
    END
  END dac_gp[69]
  PIN dac_gp[6]
    DIRECTION OUTPUT ;
    USE SIGNAL ;
    ANTENNADIFFAREA 0.948400 ;
    PORT
      LAYER Metal2 ;
        RECT 64.960 99.920 65.520 101.920 ;
    END
  END dac_gp[6]
  PIN dac_gp[70]
    DIRECTION OUTPUT ;
    USE SIGNAL ;
    ANTENNADIFFAREA 0.948400 ;
    PORT
      LAYER Metal2 ;
        RECT 277.760 0.000 278.320 2.000 ;
    END
  END dac_gp[70]
  PIN dac_gp[71]
    DIRECTION OUTPUT ;
    USE SIGNAL ;
    ANTENNADIFFAREA 0.948400 ;
    PORT
      LAYER Metal2 ;
        RECT 271.600 0.000 272.160 2.000 ;
    END
  END dac_gp[71]
  PIN dac_gp[72]
    DIRECTION OUTPUT ;
    USE SIGNAL ;
    ANTENNADIFFAREA 0.948400 ;
    PORT
      LAYER Metal2 ;
        RECT 574.560 0.000 575.120 2.000 ;
    END
  END dac_gp[72]
  PIN dac_gp[73]
    DIRECTION OUTPUT ;
    USE SIGNAL ;
    ANTENNADIFFAREA 0.948400 ;
    PORT
      LAYER Metal2 ;
        RECT 568.960 0.000 569.520 2.000 ;
    END
  END dac_gp[73]
  PIN dac_gp[74]
    DIRECTION OUTPUT ;
    USE SIGNAL ;
    ANTENNADIFFAREA 0.948400 ;
    PORT
      LAYER Metal2 ;
        RECT 562.800 0.000 563.360 2.000 ;
    END
  END dac_gp[74]
  PIN dac_gp[75]
    DIRECTION OUTPUT ;
    USE SIGNAL ;
    ANTENNADIFFAREA 0.948400 ;
    PORT
      LAYER Metal2 ;
        RECT 556.640 0.000 557.200 2.000 ;
    END
  END dac_gp[75]
  PIN dac_gp[76]
    DIRECTION OUTPUT ;
    USE SIGNAL ;
    ANTENNADIFFAREA 0.948400 ;
    PORT
      LAYER Metal2 ;
        RECT 550.480 0.000 551.040 2.000 ;
    END
  END dac_gp[76]
  PIN dac_gp[77]
    DIRECTION OUTPUT ;
    USE SIGNAL ;
    ANTENNADIFFAREA 0.948400 ;
    PORT
      LAYER Metal2 ;
        RECT 544.880 0.000 545.440 2.000 ;
    END
  END dac_gp[77]
  PIN dac_gp[78]
    DIRECTION OUTPUT ;
    USE SIGNAL ;
    ANTENNADIFFAREA 0.948400 ;
    PORT
      LAYER Metal2 ;
        RECT 538.720 0.000 539.280 2.000 ;
    END
  END dac_gp[78]
  PIN dac_gp[79]
    DIRECTION OUTPUT ;
    USE SIGNAL ;
    ANTENNADIFFAREA 0.948400 ;
    PORT
      LAYER Metal2 ;
        RECT 532.560 0.000 533.120 2.000 ;
    END
  END dac_gp[79]
  PIN dac_gp[7]
    DIRECTION OUTPUT ;
    USE SIGNAL ;
    ANTENNADIFFAREA 0.948400 ;
    PORT
      LAYER Metal2 ;
        RECT 58.800 99.920 59.360 101.920 ;
    END
  END dac_gp[7]
  PIN dac_gp[80]
    DIRECTION OUTPUT ;
    USE SIGNAL ;
    ANTENNADIFFAREA 0.948400 ;
    PORT
      LAYER Metal2 ;
        RECT 526.960 0.000 527.520 2.000 ;
    END
  END dac_gp[80]
  PIN dac_gp[81]
    DIRECTION OUTPUT ;
    USE SIGNAL ;
    ANTENNADIFFAREA 0.948400 ;
    PORT
      LAYER Metal2 ;
        RECT 520.800 0.000 521.360 2.000 ;
    END
  END dac_gp[81]
  PIN dac_gp[82]
    DIRECTION OUTPUT ;
    USE SIGNAL ;
    ANTENNADIFFAREA 0.948400 ;
    PORT
      LAYER Metal2 ;
        RECT 514.640 0.000 515.200 2.000 ;
    END
  END dac_gp[82]
  PIN dac_gp[83]
    DIRECTION OUTPUT ;
    USE SIGNAL ;
    ANTENNADIFFAREA 0.948400 ;
    PORT
      LAYER Metal2 ;
        RECT 508.480 0.000 509.040 2.000 ;
    END
  END dac_gp[83]
  PIN dac_gp[84]
    DIRECTION OUTPUT ;
    USE SIGNAL ;
    ANTENNADIFFAREA 0.948400 ;
    PORT
      LAYER Metal2 ;
        RECT 812.000 0.000 812.560 2.000 ;
    END
  END dac_gp[84]
  PIN dac_gp[85]
    DIRECTION OUTPUT ;
    USE SIGNAL ;
    ANTENNADIFFAREA 0.948400 ;
    PORT
      LAYER Metal2 ;
        RECT 805.840 0.000 806.400 2.000 ;
    END
  END dac_gp[85]
  PIN dac_gp[86]
    DIRECTION OUTPUT ;
    USE SIGNAL ;
    ANTENNADIFFAREA 0.948400 ;
    PORT
      LAYER Metal2 ;
        RECT 799.680 0.000 800.240 2.000 ;
    END
  END dac_gp[86]
  PIN dac_gp[87]
    DIRECTION OUTPUT ;
    USE SIGNAL ;
    ANTENNADIFFAREA 0.948400 ;
    PORT
      LAYER Metal2 ;
        RECT 793.520 0.000 794.080 2.000 ;
    END
  END dac_gp[87]
  PIN dac_gp[88]
    DIRECTION OUTPUT ;
    USE SIGNAL ;
    ANTENNADIFFAREA 0.948400 ;
    PORT
      LAYER Metal2 ;
        RECT 787.920 0.000 788.480 2.000 ;
    END
  END dac_gp[88]
  PIN dac_gp[89]
    DIRECTION OUTPUT ;
    USE SIGNAL ;
    ANTENNADIFFAREA 0.948400 ;
    PORT
      LAYER Metal2 ;
        RECT 781.760 0.000 782.320 2.000 ;
    END
  END dac_gp[89]
  PIN dac_gp[8]
    DIRECTION OUTPUT ;
    USE SIGNAL ;
    ANTENNADIFFAREA 0.948400 ;
    PORT
      LAYER Metal2 ;
        RECT 52.640 99.920 53.200 101.920 ;
    END
  END dac_gp[8]
  PIN dac_gp[90]
    DIRECTION OUTPUT ;
    USE SIGNAL ;
    ANTENNADIFFAREA 0.948400 ;
    PORT
      LAYER Metal2 ;
        RECT 775.600 0.000 776.160 2.000 ;
    END
  END dac_gp[90]
  PIN dac_gp[91]
    DIRECTION OUTPUT ;
    USE SIGNAL ;
    ANTENNADIFFAREA 0.948400 ;
    PORT
      LAYER Metal2 ;
        RECT 769.440 0.000 770.000 2.000 ;
    END
  END dac_gp[91]
  PIN dac_gp[92]
    DIRECTION OUTPUT ;
    USE SIGNAL ;
    ANTENNADIFFAREA 0.948400 ;
    PORT
      LAYER Metal2 ;
        RECT 763.840 0.000 764.400 2.000 ;
    END
  END dac_gp[92]
  PIN dac_gp[93]
    DIRECTION OUTPUT ;
    USE SIGNAL ;
    ANTENNADIFFAREA 0.948400 ;
    PORT
      LAYER Metal2 ;
        RECT 757.680 0.000 758.240 2.000 ;
    END
  END dac_gp[93]
  PIN dac_gp[94]
    DIRECTION OUTPUT ;
    USE SIGNAL ;
    ANTENNADIFFAREA 0.948400 ;
    PORT
      LAYER Metal2 ;
        RECT 751.520 0.000 752.080 2.000 ;
    END
  END dac_gp[94]
  PIN dac_gp[95]
    DIRECTION OUTPUT ;
    USE SIGNAL ;
    ANTENNADIFFAREA 0.948400 ;
    PORT
      LAYER Metal2 ;
        RECT 745.920 0.000 746.480 2.000 ;
    END
  END dac_gp[95]
  PIN dac_gp[9]
    DIRECTION OUTPUT ;
    USE SIGNAL ;
    ANTENNADIFFAREA 0.948400 ;
    PORT
      LAYER Metal2 ;
        RECT 46.480 99.920 47.040 101.920 ;
    END
  END dac_gp[9]
  PIN rst_amp_o
    DIRECTION OUTPUT ;
    USE SIGNAL ;
    ANTENNAGATEAREA 2.159000 ;
    ANTENNADIFFAREA 0.893200 ;
    PORT
      LAYER Metal3 ;
        RECT 0.000 76.160 2.000 76.720 ;
    END
  END rst_amp_o
  PIN rst_sw[0]
    DIRECTION OUTPUT ;
    USE SIGNAL ;
    ANTENNADIFFAREA 1.182800 ;
    PORT
      LAYER Metal2 ;
        RECT 19.600 99.920 20.160 101.920 ;
    END
  END rst_sw[0]
  PIN rst_sw[1]
    DIRECTION OUTPUT ;
    USE SIGNAL ;
    ANTENNADIFFAREA 1.182800 ;
    PORT
      LAYER Metal2 ;
        RECT 256.480 99.920 257.040 101.920 ;
    END
  END rst_sw[1]
  PIN rst_sw[2]
    DIRECTION OUTPUT ;
    USE SIGNAL ;
    ANTENNADIFFAREA 2.080400 ;
    PORT
      LAYER Metal2 ;
        RECT 493.920 99.920 494.480 101.920 ;
    END
  END rst_sw[2]
  PIN rst_sw[3]
    DIRECTION OUTPUT ;
    USE SIGNAL ;
    ANTENNADIFFAREA 1.182800 ;
    PORT
      LAYER Metal2 ;
        RECT 730.800 99.920 731.360 101.920 ;
    END
  END rst_sw[3]
  PIN rst_sw[4]
    DIRECTION OUTPUT ;
    USE SIGNAL ;
    ANTENNADIFFAREA 2.080400 ;
    PORT
      LAYER Metal2 ;
        RECT 19.600 0.000 20.160 2.000 ;
    END
  END rst_sw[4]
  PIN rst_sw[5]
    DIRECTION OUTPUT ;
    USE SIGNAL ;
    ANTENNADIFFAREA 1.182800 ;
    PORT
      LAYER Metal2 ;
        RECT 256.480 0.000 257.040 2.000 ;
    END
  END rst_sw[5]
  PIN rst_sw[6]
    DIRECTION OUTPUT ;
    USE SIGNAL ;
    ANTENNADIFFAREA 1.182800 ;
    PORT
      LAYER Metal2 ;
        RECT 493.920 0.000 494.480 2.000 ;
    END
  END rst_sw[6]
  PIN rst_sw[7]
    DIRECTION OUTPUT ;
    USE SIGNAL ;
    ANTENNADIFFAREA 1.182800 ;
    PORT
      LAYER Metal2 ;
        RECT 730.800 0.000 731.360 2.000 ;
    END
  END rst_sw[7]
  PIN sw_ipg[0]
    DIRECTION OUTPUT ;
    USE SIGNAL ;
    ANTENNADIFFAREA 2.256000 ;
    PORT
      LAYER Metal2 ;
        RECT 13.440 99.920 14.000 101.920 ;
    END
  END sw_ipg[0]
  PIN sw_ipg[1]
    DIRECTION OUTPUT ;
    USE SIGNAL ;
    ANTENNADIFFAREA 2.256000 ;
    PORT
      LAYER Metal2 ;
        RECT 250.880 99.920 251.440 101.920 ;
    END
  END sw_ipg[1]
  PIN sw_ipg[2]
    DIRECTION OUTPUT ;
    USE SIGNAL ;
    ANTENNADIFFAREA 2.256000 ;
    PORT
      LAYER Metal2 ;
        RECT 487.760 99.920 488.320 101.920 ;
    END
  END sw_ipg[2]
  PIN sw_ipg[3]
    DIRECTION OUTPUT ;
    USE SIGNAL ;
    ANTENNADIFFAREA 2.256000 ;
    PORT
      LAYER Metal2 ;
        RECT 724.640 99.920 725.200 101.920 ;
    END
  END sw_ipg[3]
  PIN sw_ipg[4]
    DIRECTION OUTPUT ;
    USE SIGNAL ;
    ANTENNADIFFAREA 2.256000 ;
    PORT
      LAYER Metal2 ;
        RECT 13.440 0.000 14.000 2.000 ;
    END
  END sw_ipg[4]
  PIN sw_ipg[5]
    DIRECTION OUTPUT ;
    USE SIGNAL ;
    ANTENNADIFFAREA 2.256000 ;
    PORT
      LAYER Metal2 ;
        RECT 250.880 0.000 251.440 2.000 ;
    END
  END sw_ipg[5]
  PIN sw_ipg[6]
    DIRECTION OUTPUT ;
    USE SIGNAL ;
    ANTENNADIFFAREA 2.256000 ;
    PORT
      LAYER Metal2 ;
        RECT 487.760 0.000 488.320 2.000 ;
    END
  END sw_ipg[6]
  PIN sw_ipg[7]
    DIRECTION OUTPUT ;
    USE SIGNAL ;
    ANTENNADIFFAREA 2.256000 ;
    PORT
      LAYER Metal2 ;
        RECT 724.640 0.000 725.200 2.000 ;
    END
  END sw_ipg[7]
  PIN sw_ipg_b[0]
    DIRECTION OUTPUT ;
    USE SIGNAL ;
    ANTENNADIFFAREA 4.408000 ;
    PORT
      LAYER Metal2 ;
        RECT 16.800 99.920 17.360 101.920 ;
    END
  END sw_ipg_b[0]
  PIN sw_ipg_b[1]
    DIRECTION OUTPUT ;
    USE SIGNAL ;
    ANTENNADIFFAREA 4.408000 ;
    PORT
      LAYER Metal2 ;
        RECT 253.680 99.920 254.240 101.920 ;
    END
  END sw_ipg_b[1]
  PIN sw_ipg_b[2]
    DIRECTION OUTPUT ;
    USE SIGNAL ;
    ANTENNADIFFAREA 4.408000 ;
    PORT
      LAYER Metal2 ;
        RECT 490.560 99.920 491.120 101.920 ;
    END
  END sw_ipg_b[2]
  PIN sw_ipg_b[3]
    DIRECTION OUTPUT ;
    USE SIGNAL ;
    ANTENNADIFFAREA 4.408000 ;
    PORT
      LAYER Metal2 ;
        RECT 728.000 99.920 728.560 101.920 ;
    END
  END sw_ipg_b[3]
  PIN sw_ipg_b[4]
    DIRECTION OUTPUT ;
    USE SIGNAL ;
    ANTENNADIFFAREA 4.408000 ;
    PORT
      LAYER Metal2 ;
        RECT 16.800 0.000 17.360 2.000 ;
    END
  END sw_ipg_b[4]
  PIN sw_ipg_b[5]
    DIRECTION OUTPUT ;
    USE SIGNAL ;
    ANTENNADIFFAREA 4.408000 ;
    PORT
      LAYER Metal2 ;
        RECT 253.680 0.000 254.240 2.000 ;
    END
  END sw_ipg_b[5]
  PIN sw_ipg_b[6]
    DIRECTION OUTPUT ;
    USE SIGNAL ;
    ANTENNADIFFAREA 4.408000 ;
    PORT
      LAYER Metal2 ;
        RECT 490.560 0.000 491.120 2.000 ;
    END
  END sw_ipg_b[6]
  PIN sw_ipg_b[7]
    DIRECTION OUTPUT ;
    USE SIGNAL ;
    ANTENNADIFFAREA 4.408000 ;
    PORT
      LAYER Metal2 ;
        RECT 728.000 0.000 728.560 2.000 ;
    END
  END sw_ipg_b[7]
  PIN sw_rec[0]
    DIRECTION OUTPUT ;
    USE SIGNAL ;
    ANTENNADIFFAREA 2.256000 ;
    PORT
      LAYER Metal2 ;
        RECT 7.840 99.920 8.400 101.920 ;
    END
  END sw_rec[0]
  PIN sw_rec[1]
    DIRECTION OUTPUT ;
    USE SIGNAL ;
    ANTENNADIFFAREA 2.256000 ;
    PORT
      LAYER Metal2 ;
        RECT 244.720 99.920 245.280 101.920 ;
    END
  END sw_rec[1]
  PIN sw_rec[2]
    DIRECTION OUTPUT ;
    USE SIGNAL ;
    ANTENNADIFFAREA 2.256000 ;
    PORT
      LAYER Metal2 ;
        RECT 481.600 99.920 482.160 101.920 ;
    END
  END sw_rec[2]
  PIN sw_rec[3]
    DIRECTION OUTPUT ;
    USE SIGNAL ;
    ANTENNADIFFAREA 2.256000 ;
    PORT
      LAYER Metal2 ;
        RECT 718.480 99.920 719.040 101.920 ;
    END
  END sw_rec[3]
  PIN sw_rec[4]
    DIRECTION OUTPUT ;
    USE SIGNAL ;
    ANTENNADIFFAREA 2.256000 ;
    PORT
      LAYER Metal2 ;
        RECT 7.840 0.000 8.400 2.000 ;
    END
  END sw_rec[4]
  PIN sw_rec[5]
    DIRECTION OUTPUT ;
    USE SIGNAL ;
    ANTENNADIFFAREA 2.256000 ;
    PORT
      LAYER Metal2 ;
        RECT 244.720 0.000 245.280 2.000 ;
    END
  END sw_rec[5]
  PIN sw_rec[6]
    DIRECTION OUTPUT ;
    USE SIGNAL ;
    ANTENNADIFFAREA 2.256000 ;
    PORT
      LAYER Metal2 ;
        RECT 481.600 0.000 482.160 2.000 ;
    END
  END sw_rec[6]
  PIN sw_rec[7]
    DIRECTION OUTPUT ;
    USE SIGNAL ;
    ANTENNADIFFAREA 2.256000 ;
    PORT
      LAYER Metal2 ;
        RECT 718.480 0.000 719.040 2.000 ;
    END
  END sw_rec[7]
  PIN sw_rec_b[0]
    DIRECTION OUTPUT ;
    USE SIGNAL ;
    ANTENNADIFFAREA 4.408000 ;
    PORT
      LAYER Metal2 ;
        RECT 10.640 99.920 11.200 101.920 ;
    END
  END sw_rec_b[0]
  PIN sw_rec_b[1]
    DIRECTION OUTPUT ;
    USE SIGNAL ;
    ANTENNADIFFAREA 4.408000 ;
    PORT
      LAYER Metal2 ;
        RECT 247.520 99.920 248.080 101.920 ;
    END
  END sw_rec_b[1]
  PIN sw_rec_b[2]
    DIRECTION OUTPUT ;
    USE SIGNAL ;
    ANTENNADIFFAREA 4.408000 ;
    PORT
      LAYER Metal2 ;
        RECT 484.960 99.920 485.520 101.920 ;
    END
  END sw_rec_b[2]
  PIN sw_rec_b[3]
    DIRECTION OUTPUT ;
    USE SIGNAL ;
    ANTENNADIFFAREA 4.408000 ;
    PORT
      LAYER Metal2 ;
        RECT 721.840 99.920 722.400 101.920 ;
    END
  END sw_rec_b[3]
  PIN sw_rec_b[4]
    DIRECTION OUTPUT ;
    USE SIGNAL ;
    ANTENNADIFFAREA 4.408000 ;
    PORT
      LAYER Metal2 ;
        RECT 10.640 0.000 11.200 2.000 ;
    END
  END sw_rec_b[4]
  PIN sw_rec_b[5]
    DIRECTION OUTPUT ;
    USE SIGNAL ;
    ANTENNADIFFAREA 4.408000 ;
    PORT
      LAYER Metal2 ;
        RECT 247.520 0.000 248.080 2.000 ;
    END
  END sw_rec_b[5]
  PIN sw_rec_b[6]
    DIRECTION OUTPUT ;
    USE SIGNAL ;
    ANTENNADIFFAREA 4.408000 ;
    PORT
      LAYER Metal2 ;
        RECT 484.960 0.000 485.520 2.000 ;
    END
  END sw_rec_b[6]
  PIN sw_rec_b[7]
    DIRECTION OUTPUT ;
    USE SIGNAL ;
    ANTENNADIFFAREA 4.408000 ;
    PORT
      LAYER Metal2 ;
        RECT 721.840 0.000 722.400 2.000 ;
    END
  END sw_rec_b[7]
  PIN tg_on[0]
    DIRECTION OUTPUT ;
    USE SIGNAL ;
    ANTENNAGATEAREA 0.898000 ;
    ANTENNADIFFAREA 0.897600 ;
    PORT
      LAYER Metal2 ;
        RECT 22.960 99.920 23.520 101.920 ;
    END
  END tg_on[0]
  PIN tg_on[1]
    DIRECTION OUTPUT ;
    USE SIGNAL ;
    ANTENNAGATEAREA 0.898000 ;
    ANTENNADIFFAREA 0.897600 ;
    PORT
      LAYER Metal2 ;
        RECT 259.840 99.920 260.400 101.920 ;
    END
  END tg_on[1]
  PIN tg_on[2]
    DIRECTION OUTPUT ;
    USE SIGNAL ;
    ANTENNAGATEAREA 0.898000 ;
    ANTENNADIFFAREA 0.897600 ;
    PORT
      LAYER Metal2 ;
        RECT 496.720 99.920 497.280 101.920 ;
    END
  END tg_on[2]
  PIN tg_on[3]
    DIRECTION OUTPUT ;
    USE SIGNAL ;
    ANTENNAGATEAREA 0.898000 ;
    ANTENNADIFFAREA 0.897600 ;
    PORT
      LAYER Metal2 ;
        RECT 733.600 99.920 734.160 101.920 ;
    END
  END tg_on[3]
  PIN tg_on[4]
    DIRECTION OUTPUT ;
    USE SIGNAL ;
    ANTENNAGATEAREA 0.898000 ;
    ANTENNADIFFAREA 0.897600 ;
    PORT
      LAYER Metal2 ;
        RECT 22.960 0.000 23.520 2.000 ;
    END
  END tg_on[4]
  PIN tg_on[5]
    DIRECTION OUTPUT ;
    USE SIGNAL ;
    ANTENNAGATEAREA 0.898000 ;
    ANTENNADIFFAREA 0.897600 ;
    PORT
      LAYER Metal2 ;
        RECT 259.840 0.000 260.400 2.000 ;
    END
  END tg_on[5]
  PIN tg_on[6]
    DIRECTION OUTPUT ;
    USE SIGNAL ;
    ANTENNAGATEAREA 0.898000 ;
    ANTENNADIFFAREA 0.897600 ;
    PORT
      LAYER Metal2 ;
        RECT 496.720 0.000 497.280 2.000 ;
    END
  END tg_on[6]
  PIN tg_on[7]
    DIRECTION OUTPUT ;
    USE SIGNAL ;
    ANTENNAGATEAREA 0.898000 ;
    ANTENNADIFFAREA 0.897600 ;
    PORT
      LAYER Metal2 ;
        RECT 733.600 0.000 734.160 2.000 ;
    END
  END tg_on[7]
  OBS
      LAYER Nwell ;
        RECT 6.290 3.490 813.550 98.430 ;
      LAYER Metal1 ;
        RECT 6.720 3.620 813.120 98.300 ;
      LAYER Metal2 ;
        RECT 0.140 99.620 7.540 100.710 ;
        RECT 8.700 99.620 10.340 100.710 ;
        RECT 11.500 99.620 13.140 100.710 ;
        RECT 14.300 99.620 16.500 100.710 ;
        RECT 17.660 99.620 19.300 100.710 ;
        RECT 20.460 99.620 22.660 100.710 ;
        RECT 23.820 99.620 25.460 100.710 ;
        RECT 26.620 99.620 28.260 100.710 ;
        RECT 29.420 99.620 31.620 100.710 ;
        RECT 32.780 99.620 34.420 100.710 ;
        RECT 35.580 99.620 37.220 100.710 ;
        RECT 38.380 99.620 40.580 100.710 ;
        RECT 41.740 99.620 43.380 100.710 ;
        RECT 44.540 99.620 46.180 100.710 ;
        RECT 47.340 99.620 49.540 100.710 ;
        RECT 50.700 99.620 52.340 100.710 ;
        RECT 53.500 99.620 55.140 100.710 ;
        RECT 56.300 99.620 58.500 100.710 ;
        RECT 59.660 99.620 61.300 100.710 ;
        RECT 62.460 99.620 64.660 100.710 ;
        RECT 65.820 99.620 67.460 100.710 ;
        RECT 68.620 99.620 70.260 100.710 ;
        RECT 71.420 99.620 73.620 100.710 ;
        RECT 74.780 99.620 76.420 100.710 ;
        RECT 77.580 99.620 79.220 100.710 ;
        RECT 80.380 99.620 82.580 100.710 ;
        RECT 83.740 99.620 85.380 100.710 ;
        RECT 86.540 99.620 88.180 100.710 ;
        RECT 89.340 99.620 91.540 100.710 ;
        RECT 92.700 99.620 94.340 100.710 ;
        RECT 95.500 99.620 97.140 100.710 ;
        RECT 98.300 99.620 100.500 100.710 ;
        RECT 101.660 99.620 103.300 100.710 ;
        RECT 104.460 99.620 244.420 100.710 ;
        RECT 245.580 99.620 247.220 100.710 ;
        RECT 248.380 99.620 250.580 100.710 ;
        RECT 251.740 99.620 253.380 100.710 ;
        RECT 254.540 99.620 256.180 100.710 ;
        RECT 257.340 99.620 259.540 100.710 ;
        RECT 260.700 99.620 262.340 100.710 ;
        RECT 263.500 99.620 265.140 100.710 ;
        RECT 266.300 99.620 268.500 100.710 ;
        RECT 269.660 99.620 271.300 100.710 ;
        RECT 272.460 99.620 274.660 100.710 ;
        RECT 275.820 99.620 277.460 100.710 ;
        RECT 278.620 99.620 280.260 100.710 ;
        RECT 281.420 99.620 283.620 100.710 ;
        RECT 284.780 99.620 286.420 100.710 ;
        RECT 287.580 99.620 289.220 100.710 ;
        RECT 290.380 99.620 292.580 100.710 ;
        RECT 293.740 99.620 295.380 100.710 ;
        RECT 296.540 99.620 298.180 100.710 ;
        RECT 299.340 99.620 301.540 100.710 ;
        RECT 302.700 99.620 304.340 100.710 ;
        RECT 305.500 99.620 307.700 100.710 ;
        RECT 308.860 99.620 310.500 100.710 ;
        RECT 311.660 99.620 313.300 100.710 ;
        RECT 314.460 99.620 316.660 100.710 ;
        RECT 317.820 99.620 319.460 100.710 ;
        RECT 320.620 99.620 322.260 100.710 ;
        RECT 323.420 99.620 325.620 100.710 ;
        RECT 326.780 99.620 328.420 100.710 ;
        RECT 329.580 99.620 331.220 100.710 ;
        RECT 332.380 99.620 334.580 100.710 ;
        RECT 335.740 99.620 337.380 100.710 ;
        RECT 338.540 99.620 340.180 100.710 ;
        RECT 341.340 99.620 481.300 100.710 ;
        RECT 482.460 99.620 484.660 100.710 ;
        RECT 485.820 99.620 487.460 100.710 ;
        RECT 488.620 99.620 490.260 100.710 ;
        RECT 491.420 99.620 493.620 100.710 ;
        RECT 494.780 99.620 496.420 100.710 ;
        RECT 497.580 99.620 499.220 100.710 ;
        RECT 500.380 99.620 502.580 100.710 ;
        RECT 503.740 99.620 505.380 100.710 ;
        RECT 506.540 99.620 508.180 100.710 ;
        RECT 509.340 99.620 511.540 100.710 ;
        RECT 512.700 99.620 514.340 100.710 ;
        RECT 515.500 99.620 517.140 100.710 ;
        RECT 518.300 99.620 520.500 100.710 ;
        RECT 521.660 99.620 523.300 100.710 ;
        RECT 524.460 99.620 526.660 100.710 ;
        RECT 527.820 99.620 529.460 100.710 ;
        RECT 530.620 99.620 532.260 100.710 ;
        RECT 533.420 99.620 535.620 100.710 ;
        RECT 536.780 99.620 538.420 100.710 ;
        RECT 539.580 99.620 541.220 100.710 ;
        RECT 542.380 99.620 544.580 100.710 ;
        RECT 545.740 99.620 547.380 100.710 ;
        RECT 548.540 99.620 550.180 100.710 ;
        RECT 551.340 99.620 553.540 100.710 ;
        RECT 554.700 99.620 556.340 100.710 ;
        RECT 557.500 99.620 559.700 100.710 ;
        RECT 560.860 99.620 562.500 100.710 ;
        RECT 563.660 99.620 565.300 100.710 ;
        RECT 566.460 99.620 568.660 100.710 ;
        RECT 569.820 99.620 571.460 100.710 ;
        RECT 572.620 99.620 574.260 100.710 ;
        RECT 575.420 99.620 577.620 100.710 ;
        RECT 578.780 99.620 718.180 100.710 ;
        RECT 719.340 99.620 721.540 100.710 ;
        RECT 722.700 99.620 724.340 100.710 ;
        RECT 725.500 99.620 727.700 100.710 ;
        RECT 728.860 99.620 730.500 100.710 ;
        RECT 731.660 99.620 733.300 100.710 ;
        RECT 734.460 99.620 736.660 100.710 ;
        RECT 737.820 99.620 739.460 100.710 ;
        RECT 740.620 99.620 742.260 100.710 ;
        RECT 743.420 99.620 745.620 100.710 ;
        RECT 746.780 99.620 748.420 100.710 ;
        RECT 749.580 99.620 751.220 100.710 ;
        RECT 752.380 99.620 754.580 100.710 ;
        RECT 755.740 99.620 757.380 100.710 ;
        RECT 758.540 99.620 760.180 100.710 ;
        RECT 761.340 99.620 763.540 100.710 ;
        RECT 764.700 99.620 766.340 100.710 ;
        RECT 767.500 99.620 769.140 100.710 ;
        RECT 770.300 99.620 772.500 100.710 ;
        RECT 773.660 99.620 775.300 100.710 ;
        RECT 776.460 99.620 778.660 100.710 ;
        RECT 779.820 99.620 781.460 100.710 ;
        RECT 782.620 99.620 784.260 100.710 ;
        RECT 785.420 99.620 787.620 100.710 ;
        RECT 788.780 99.620 790.420 100.710 ;
        RECT 791.580 99.620 793.220 100.710 ;
        RECT 794.380 99.620 796.580 100.710 ;
        RECT 797.740 99.620 799.380 100.710 ;
        RECT 800.540 99.620 802.180 100.710 ;
        RECT 803.340 99.620 805.540 100.710 ;
        RECT 806.700 99.620 808.340 100.710 ;
        RECT 809.500 99.620 811.700 100.710 ;
        RECT 812.860 99.620 814.500 100.710 ;
        RECT 0.140 2.300 815.220 99.620 ;
        RECT 0.140 0.090 7.540 2.300 ;
        RECT 8.700 0.090 10.340 2.300 ;
        RECT 11.500 0.090 13.140 2.300 ;
        RECT 14.300 0.090 16.500 2.300 ;
        RECT 17.660 0.090 19.300 2.300 ;
        RECT 20.460 0.090 22.660 2.300 ;
        RECT 23.820 0.090 25.460 2.300 ;
        RECT 26.620 0.090 28.260 2.300 ;
        RECT 29.420 0.090 31.620 2.300 ;
        RECT 32.780 0.090 34.420 2.300 ;
        RECT 35.580 0.090 37.220 2.300 ;
        RECT 38.380 0.090 40.580 2.300 ;
        RECT 41.740 0.090 43.380 2.300 ;
        RECT 44.540 0.090 46.180 2.300 ;
        RECT 47.340 0.090 49.540 2.300 ;
        RECT 50.700 0.090 52.340 2.300 ;
        RECT 53.500 0.090 55.140 2.300 ;
        RECT 56.300 0.090 58.500 2.300 ;
        RECT 59.660 0.090 61.300 2.300 ;
        RECT 62.460 0.090 64.660 2.300 ;
        RECT 65.820 0.090 67.460 2.300 ;
        RECT 68.620 0.090 70.260 2.300 ;
        RECT 71.420 0.090 73.620 2.300 ;
        RECT 74.780 0.090 76.420 2.300 ;
        RECT 77.580 0.090 79.220 2.300 ;
        RECT 80.380 0.090 82.580 2.300 ;
        RECT 83.740 0.090 85.380 2.300 ;
        RECT 86.540 0.090 88.180 2.300 ;
        RECT 89.340 0.090 91.540 2.300 ;
        RECT 92.700 0.090 94.340 2.300 ;
        RECT 95.500 0.090 97.140 2.300 ;
        RECT 98.300 0.090 100.500 2.300 ;
        RECT 101.660 0.090 103.300 2.300 ;
        RECT 104.460 0.090 244.420 2.300 ;
        RECT 245.580 0.090 247.220 2.300 ;
        RECT 248.380 0.090 250.580 2.300 ;
        RECT 251.740 0.090 253.380 2.300 ;
        RECT 254.540 0.090 256.180 2.300 ;
        RECT 257.340 0.090 259.540 2.300 ;
        RECT 260.700 0.090 262.340 2.300 ;
        RECT 263.500 0.090 265.140 2.300 ;
        RECT 266.300 0.090 268.500 2.300 ;
        RECT 269.660 0.090 271.300 2.300 ;
        RECT 272.460 0.090 274.660 2.300 ;
        RECT 275.820 0.090 277.460 2.300 ;
        RECT 278.620 0.090 280.260 2.300 ;
        RECT 281.420 0.090 283.620 2.300 ;
        RECT 284.780 0.090 286.420 2.300 ;
        RECT 287.580 0.090 289.220 2.300 ;
        RECT 290.380 0.090 292.580 2.300 ;
        RECT 293.740 0.090 295.380 2.300 ;
        RECT 296.540 0.090 298.180 2.300 ;
        RECT 299.340 0.090 301.540 2.300 ;
        RECT 302.700 0.090 304.340 2.300 ;
        RECT 305.500 0.090 307.700 2.300 ;
        RECT 308.860 0.090 310.500 2.300 ;
        RECT 311.660 0.090 313.300 2.300 ;
        RECT 314.460 0.090 316.660 2.300 ;
        RECT 317.820 0.090 319.460 2.300 ;
        RECT 320.620 0.090 322.260 2.300 ;
        RECT 323.420 0.090 325.620 2.300 ;
        RECT 326.780 0.090 328.420 2.300 ;
        RECT 329.580 0.090 331.220 2.300 ;
        RECT 332.380 0.090 334.580 2.300 ;
        RECT 335.740 0.090 337.380 2.300 ;
        RECT 338.540 0.090 340.180 2.300 ;
        RECT 341.340 0.090 481.300 2.300 ;
        RECT 482.460 0.090 484.660 2.300 ;
        RECT 485.820 0.090 487.460 2.300 ;
        RECT 488.620 0.090 490.260 2.300 ;
        RECT 491.420 0.090 493.620 2.300 ;
        RECT 494.780 0.090 496.420 2.300 ;
        RECT 497.580 0.090 499.220 2.300 ;
        RECT 500.380 0.090 502.580 2.300 ;
        RECT 503.740 0.090 505.380 2.300 ;
        RECT 506.540 0.090 508.180 2.300 ;
        RECT 509.340 0.090 511.540 2.300 ;
        RECT 512.700 0.090 514.340 2.300 ;
        RECT 515.500 0.090 517.140 2.300 ;
        RECT 518.300 0.090 520.500 2.300 ;
        RECT 521.660 0.090 523.300 2.300 ;
        RECT 524.460 0.090 526.660 2.300 ;
        RECT 527.820 0.090 529.460 2.300 ;
        RECT 530.620 0.090 532.260 2.300 ;
        RECT 533.420 0.090 535.620 2.300 ;
        RECT 536.780 0.090 538.420 2.300 ;
        RECT 539.580 0.090 541.220 2.300 ;
        RECT 542.380 0.090 544.580 2.300 ;
        RECT 545.740 0.090 547.380 2.300 ;
        RECT 548.540 0.090 550.180 2.300 ;
        RECT 551.340 0.090 553.540 2.300 ;
        RECT 554.700 0.090 556.340 2.300 ;
        RECT 557.500 0.090 559.700 2.300 ;
        RECT 560.860 0.090 562.500 2.300 ;
        RECT 563.660 0.090 565.300 2.300 ;
        RECT 566.460 0.090 568.660 2.300 ;
        RECT 569.820 0.090 571.460 2.300 ;
        RECT 572.620 0.090 574.260 2.300 ;
        RECT 575.420 0.090 577.620 2.300 ;
        RECT 578.780 0.090 718.180 2.300 ;
        RECT 719.340 0.090 721.540 2.300 ;
        RECT 722.700 0.090 724.340 2.300 ;
        RECT 725.500 0.090 727.700 2.300 ;
        RECT 728.860 0.090 730.500 2.300 ;
        RECT 731.660 0.090 733.300 2.300 ;
        RECT 734.460 0.090 736.660 2.300 ;
        RECT 737.820 0.090 739.460 2.300 ;
        RECT 740.620 0.090 742.260 2.300 ;
        RECT 743.420 0.090 745.620 2.300 ;
        RECT 746.780 0.090 748.420 2.300 ;
        RECT 749.580 0.090 751.220 2.300 ;
        RECT 752.380 0.090 754.580 2.300 ;
        RECT 755.740 0.090 757.380 2.300 ;
        RECT 758.540 0.090 760.180 2.300 ;
        RECT 761.340 0.090 763.540 2.300 ;
        RECT 764.700 0.090 766.340 2.300 ;
        RECT 767.500 0.090 769.140 2.300 ;
        RECT 770.300 0.090 772.500 2.300 ;
        RECT 773.660 0.090 775.300 2.300 ;
        RECT 776.460 0.090 778.660 2.300 ;
        RECT 779.820 0.090 781.460 2.300 ;
        RECT 782.620 0.090 784.260 2.300 ;
        RECT 785.420 0.090 787.620 2.300 ;
        RECT 788.780 0.090 790.420 2.300 ;
        RECT 791.580 0.090 793.220 2.300 ;
        RECT 794.380 0.090 796.580 2.300 ;
        RECT 797.740 0.090 799.380 2.300 ;
        RECT 800.540 0.090 802.180 2.300 ;
        RECT 803.340 0.090 805.540 2.300 ;
        RECT 806.700 0.090 808.340 2.300 ;
        RECT 809.500 0.090 811.700 2.300 ;
        RECT 812.860 0.090 814.500 2.300 ;
      LAYER Metal3 ;
        RECT 0.090 77.020 815.270 100.660 ;
        RECT 2.300 75.860 815.270 77.020 ;
        RECT 0.090 73.660 815.270 75.860 ;
        RECT 2.300 72.500 815.270 73.660 ;
        RECT 0.090 70.300 815.270 72.500 ;
        RECT 2.300 69.140 815.270 70.300 ;
        RECT 0.090 66.380 815.270 69.140 ;
        RECT 2.300 65.220 815.270 66.380 ;
        RECT 0.090 63.020 815.270 65.220 ;
        RECT 2.300 61.860 815.270 63.020 ;
        RECT 0.090 59.660 815.270 61.860 ;
        RECT 2.300 58.500 815.270 59.660 ;
        RECT 0.090 56.300 815.270 58.500 ;
        RECT 2.300 55.140 815.270 56.300 ;
        RECT 0.090 52.380 815.270 55.140 ;
        RECT 2.300 51.220 815.270 52.380 ;
        RECT 0.090 49.020 815.270 51.220 ;
        RECT 2.300 47.860 815.270 49.020 ;
        RECT 0.090 45.660 815.270 47.860 ;
        RECT 2.300 44.500 815.270 45.660 ;
        RECT 0.090 42.300 815.270 44.500 ;
        RECT 2.300 41.140 815.270 42.300 ;
        RECT 0.090 38.380 815.270 41.140 ;
        RECT 2.300 37.220 815.270 38.380 ;
        RECT 0.090 35.020 815.270 37.220 ;
        RECT 2.300 33.860 815.270 35.020 ;
        RECT 0.090 31.660 815.270 33.860 ;
        RECT 2.300 30.500 815.270 31.660 ;
        RECT 0.090 28.300 815.270 30.500 ;
        RECT 2.300 27.140 815.270 28.300 ;
        RECT 0.090 24.380 815.270 27.140 ;
        RECT 2.300 23.220 815.270 24.380 ;
        RECT 0.090 21.020 815.270 23.220 ;
        RECT 2.300 19.860 815.270 21.020 ;
        RECT 0.090 17.660 815.270 19.860 ;
        RECT 2.300 16.500 815.270 17.660 ;
        RECT 0.090 14.300 815.270 16.500 ;
        RECT 2.300 13.140 815.270 14.300 ;
        RECT 0.090 10.380 815.270 13.140 ;
        RECT 2.300 9.220 815.270 10.380 ;
        RECT 0.090 7.020 815.270 9.220 ;
        RECT 2.300 5.860 815.270 7.020 ;
        RECT 0.090 3.660 815.270 5.860 ;
        RECT 2.300 2.500 815.270 3.660 ;
        RECT 0.090 0.140 815.270 2.500 ;
      LAYER Metal4 ;
        RECT 192.780 1.770 271.060 99.030 ;
        RECT 273.260 1.770 274.360 99.030 ;
        RECT 276.560 1.770 388.660 99.030 ;
        RECT 390.860 1.770 391.960 99.030 ;
        RECT 394.160 1.770 506.260 99.030 ;
        RECT 508.460 1.770 509.560 99.030 ;
        RECT 511.760 1.770 623.860 99.030 ;
        RECT 626.060 1.770 627.160 99.030 ;
        RECT 629.360 1.770 741.460 99.030 ;
        RECT 743.660 1.770 744.660 99.030 ;
  END
END afe_dig
END LIBRARY

